FUNCTION "Gest Automatico" : VOID
TITLE =Gestione Ciclo Automatico
AUTHOR : MassimoZ
FAMILY : NovaSrl
VERSION : 0.1

BEGIN
NETWORK
TITLE =Condizioni per Ciclo

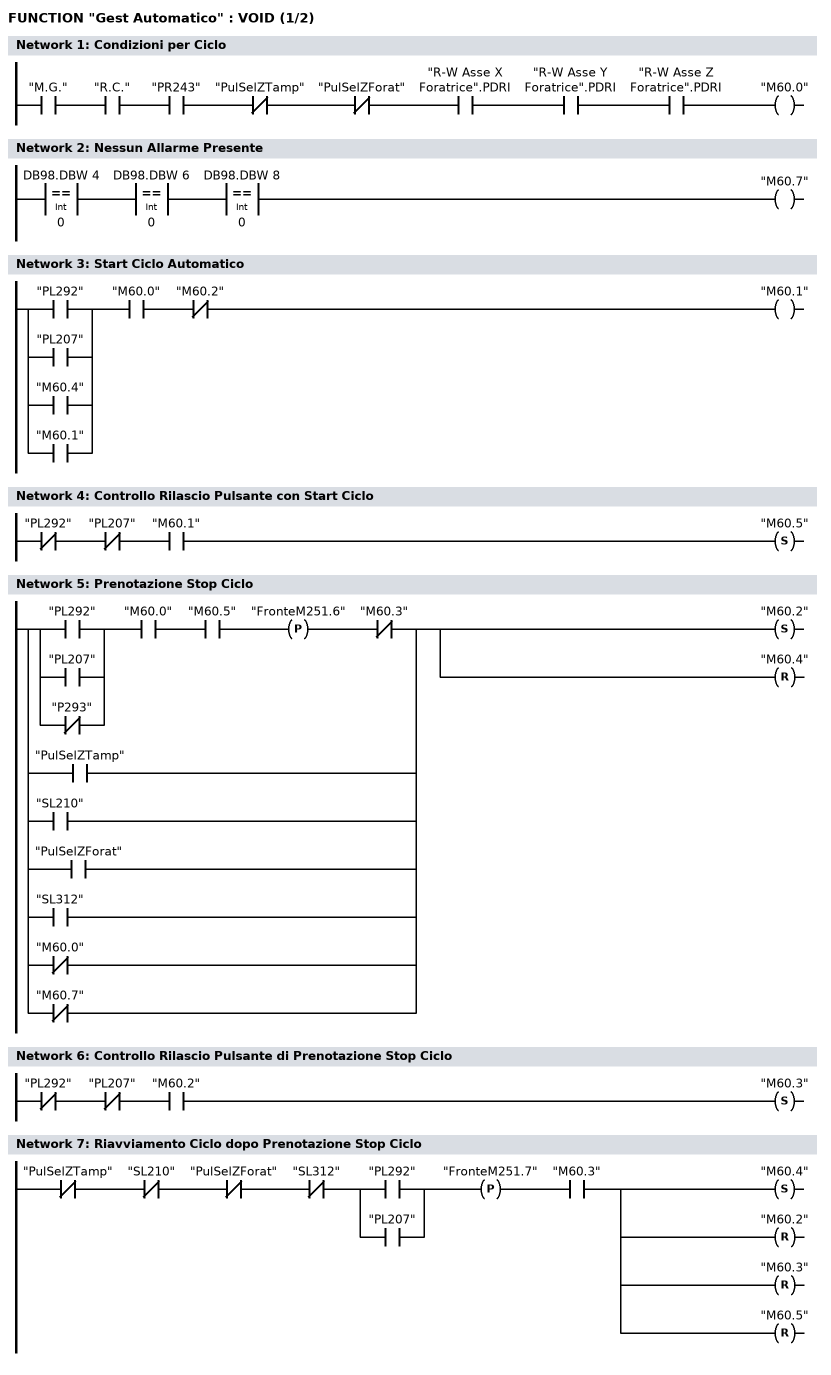
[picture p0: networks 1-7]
      U     "M.G.";
      U     "R.C.";
      U     "PR243";
      UN    "PulSelZTamp";
      UN    "PulSelZForat";
      U     "R-W Asse X Foratrice".PDRI;
      U     "R-W Asse Y Foratrice".PDRI;
      U     "R-W Asse Z Foratrice".PDRI;
      =     "M60.0";
NETWORK
TITLE =Nessun Allarme Presente

      U(    ;
      L     DB98.DBW    4;
      L     0;
      ==I   ;
      )     ;
      U(    ;
      L     DB98.DBW    6;
      L     0;
      ==I   ;
      )     ;
      U(    ;
      L     DB98.DBW    8;
      L     0;
      ==I   ;
      )     ;
      =     "M60.7";
NETWORK
TITLE =Start Ciclo Automatico

      U(    ;
      O     "PL292";
      O     "PL207";
      O     "M60.4";
      O     "M60.1";
      )     ;
      U     "M60.0";
      UN    "M60.2";
      =     "M60.1";
NETWORK
TITLE =Controllo Rilascio Pulsante con Start Ciclo

      UN    "PL292";
      UN    "PL207";
      U     "M60.1";
      S     "M60.5";
NETWORK
TITLE =Prenotazione Stop Ciclo

      U(    ;
      O     "PL292";
      O     "PL207";
      ON    "P293";
      )     ;
      U     "M60.0";
      U     "M60.5";
      FP    "FronteM251.6";
      UN    "M60.3";
      O     "PulSelZTamp";
      O     "SL210";
      O     "PulSelZForat";
      O     "SL312";
      ON    "M60.0";
      ON    "M60.7";
      S     "M60.2";
      R     "M60.4";
NETWORK
TITLE =Controllo Rilascio Pulsante di Prenotazione Stop Ciclo

      UN    "PL292";
      UN    "PL207";
      U     "M60.2";
      S     "M60.3";
NETWORK
TITLE =Riavviamento Ciclo dopo Prenotazione Stop Ciclo

      UN    "PulSelZTamp";
      UN    "SL210";
      UN    "PulSelZForat";
      UN    "SL312";
      U(    ;
      O     "PL292";
      O     "PL207";
      )     ;
      FP    "FronteM251.7";
      U     "M60.3";
      S     "M60.4";
      R     "M60.2";
      R     "M60.3";
      R     "M60.5";
NETWORK
TITLE =Svuotamento Robot Foratrice e Tampografie

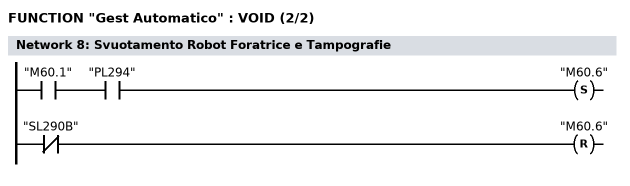
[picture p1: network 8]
      U     "M60.1";
      U     "PL294";
      S     "M60.6";
      UN    "SL290B";
      R     "M60.6";
      NOP   0;
NETWORK
TITLE ======== Ciclo Automatico Zona Foratrice =======



NETWORK
TITLE =Presenza Pezzo in Entrata Zona Foratrice

      U(    ;
      UN    "SL290";
      U     "SL290B";
      U     "FT137";
      L     S5T#1S;
      SE    T     30;
      NOP   0;
      NOP   0;
      NOP   0;
      U     T     30;
      )     ;
      L     S5T#2S;
      SA    T     31;
      NOP   0;
      NOP   0;
      NOP   0;
      U     T     31;
      =     "M61.0";
NETWORK
TITLE =Presenza Pezzo Zona Foratrice

      U(    ;
      UN    "SL290";
      U     "SL290B";
      U     "FT144";
      L     S5T#1S;
      SE    T     32;
      NOP   0;
      NOP   0;
      NOP   0;
      U     T     32;
      )     ;
      L     S5T#200MS;
      SA    T     33;
      NOP   0;
      NOP   0;
      NOP   0;
      U     T     33;
      =     "M61.1";
NETWORK
TITLE =Presenza Pezzo Zona Ribaltatore

      U(    ;
      UN    "SL290";
      U     "SL290B";
      U     "FT146";
      L     S5T#1S500MS;
      SE    T     34;
      NOP   0;
      NOP   0;
      NOP   0;
      U     T     34;
      )     ;
      L     S5T#200MS;
      SA    T     35;
      NOP   0;
      NOP   0;
      NOP   0;
      U     T     35;
      =     "M61.2";
NETWORK
TITLE =Com Aut Start Motore Nastro Orizzontale

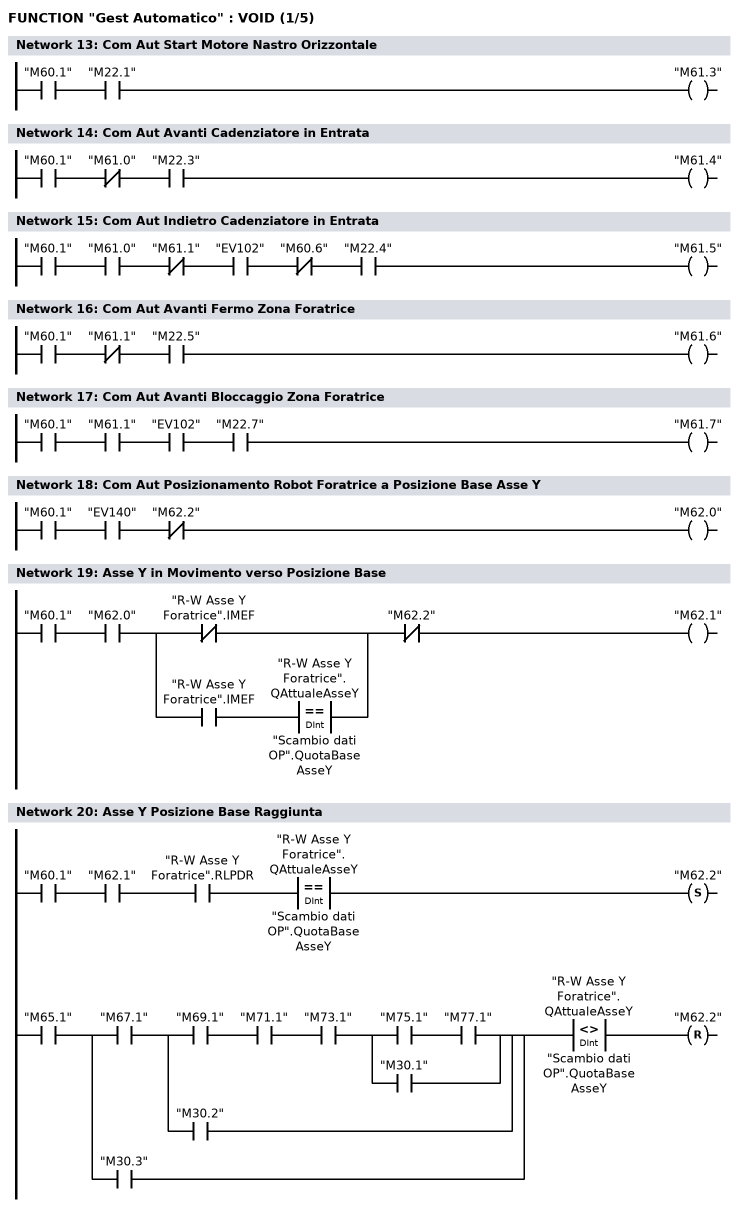
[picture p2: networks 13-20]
      U     "M60.1";
      U     "M22.1";
      =     "M61.3";
NETWORK
TITLE =Com Aut Avanti Cadenziatore in Entrata

      U     "M60.1";
      UN    "M61.0";
      U     "M22.3";
      =     "M61.4";
NETWORK
TITLE =Com Aut Indietro Cadenziatore in Entrata

      U     "M60.1";
      U     "M61.0";
      UN    "M61.1";
      U     "EV102";
      UN    "M60.6";
      U     "M22.4";
      =     "M61.5";
NETWORK
TITLE =Com Aut Avanti Fermo Zona Foratrice

      U     "M60.1";
      UN    "M61.1";
      U     "M22.5";
      =     "M61.6";
NETWORK
TITLE =Com Aut Avanti Bloccaggio Zona Foratrice

      U     "M60.1";
      U     "M61.1";
      U     "EV102";
      U     "M22.7";
      =     "M61.7";
NETWORK
TITLE =Com Aut Posizionamento Robot Foratrice a Posizione Base Asse Y

      U     "M60.1";
      U     "EV140";
      UN    "M62.2";
      =     "M62.0";
NETWORK
TITLE =Asse Y in Movimento verso Posizione Base

      U     "M60.1";
      U     "M62.0";
      U(    ;
      ON    "R-W Asse Y Foratrice".IMEF;
      O     ;
      U     "R-W Asse Y Foratrice".IMEF;
      U(    ;
      L     "R-W Asse Y Foratrice".QAttualeAsseY;
      L     "Scambio dati OP".QuotaBaseAsseY;
      ==D   ;
      )     ;
      )     ;
      UN    "M62.2";
      =     "M62.1";
NETWORK
TITLE =Asse Y Posizione Base Raggiunta

      U     "M60.1";
      U     "M62.1";
      U     "R-W Asse Y Foratrice".RLPDR;
      U(    ;
      L     "R-W Asse Y Foratrice".QAttualeAsseY;
      L     "Scambio dati OP".QuotaBaseAsseY;
      ==D   ;
      )     ;
      S     "M62.2";
      U     "M65.1";
      U(    ;
      U     "M67.1";
      U(    ;
      U     "M69.1";
      U     "M71.1";
      U     "M73.1";
      U(    ;
      U     "M75.1";
      U     "M77.1";
      O     "M30.1";
      )     ;
      O     "M30.2";
      )     ;
      O     "M30.3";
      )     ;
      U(    ;
      L     "R-W Asse Y Foratrice".QAttualeAsseY;
      L     "Scambio dati OP".QuotaBaseAsseY;
      <>D   ;
      )     ;
      R     "M62.2";
      NOP   0;
NETWORK
TITLE =Com Aut Posizionamento Robot Foratrice a Posizione Base Asse X

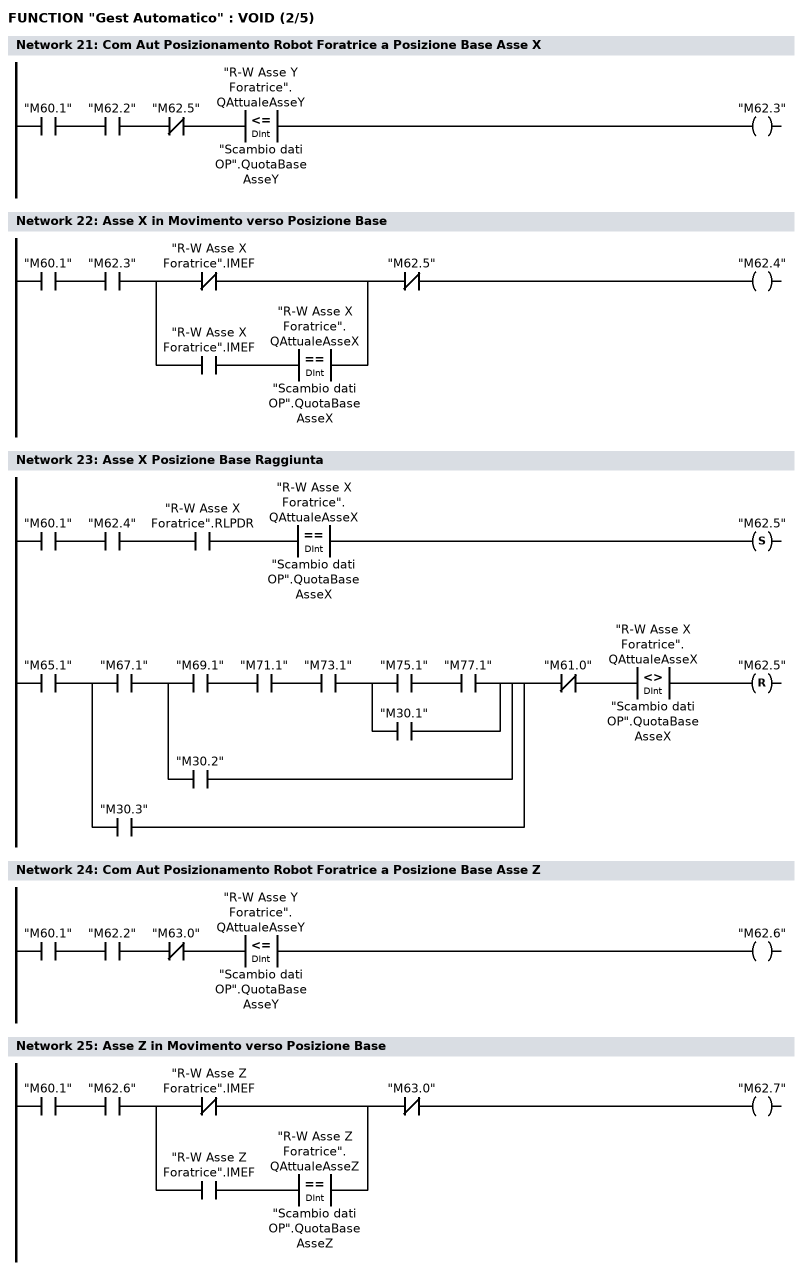
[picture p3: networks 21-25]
      U     "M60.1";
      U     "M62.2";
      UN    "M62.5";
      U(    ;
      L     "R-W Asse Y Foratrice".QAttualeAsseY;
      L     "Scambio dati OP".QuotaBaseAsseY;
      <=D   ;
      )     ;
      =     "M62.3";
NETWORK
TITLE =Asse X in Movimento verso Posizione Base

      U     "M60.1";
      U     "M62.3";
      U(    ;
      ON    "R-W Asse X Foratrice".IMEF;
      O     ;
      U     "R-W Asse X Foratrice".IMEF;
      U(    ;
      L     "R-W Asse X Foratrice".QAttualeAsseX;
      L     "Scambio dati OP".QuotaBaseAsseX;
      ==D   ;
      )     ;
      )     ;
      UN    "M62.5";
      =     "M62.4";
NETWORK
TITLE =Asse X Posizione Base Raggiunta

      U     "M60.1";
      U     "M62.4";
      U     "R-W Asse X Foratrice".RLPDR;
      U(    ;
      L     "R-W Asse X Foratrice".QAttualeAsseX;
      L     "Scambio dati OP".QuotaBaseAsseX;
      ==D   ;
      )     ;
      S     "M62.5";
      U     "M65.1";
      U(    ;
      U     "M67.1";
      U(    ;
      U     "M69.1";
      U     "M71.1";
      U     "M73.1";
      U(    ;
      U     "M75.1";
      U     "M77.1";
      O     "M30.1";
      )     ;
      O     "M30.2";
      )     ;
      O     "M30.3";
      )     ;
      UN    "M61.0";
      U(    ;
      L     "R-W Asse X Foratrice".QAttualeAsseX;
      L     "Scambio dati OP".QuotaBaseAsseX;
      <>D   ;
      )     ;
      R     "M62.5";
      NOP   0;
NETWORK
TITLE =Com Aut Posizionamento Robot Foratrice a Posizione Base Asse Z

      U     "M60.1";
      U     "M62.2";
      UN    "M63.0";
      U(    ;
      L     "R-W Asse Y Foratrice".QAttualeAsseY;
      L     "Scambio dati OP".QuotaBaseAsseY;
      <=D   ;
      )     ;
      =     "M62.6";
NETWORK
TITLE =Asse Z in Movimento verso Posizione Base

      U     "M60.1";
      U     "M62.6";
      U(    ;
      ON    "R-W Asse Z Foratrice".IMEF;
      O     ;
      U     "R-W Asse Z Foratrice".IMEF;
      U(    ;
      L     "R-W Asse Z Foratrice".QAttualeAsseZ;
      L     "Scambio dati OP".QuotaBaseAsseZ;
      ==D   ;
      )     ;
      )     ;
      UN    "M63.0";
      =     "M62.7";
NETWORK
TITLE =Asse Z Posizione Base Raggiunta

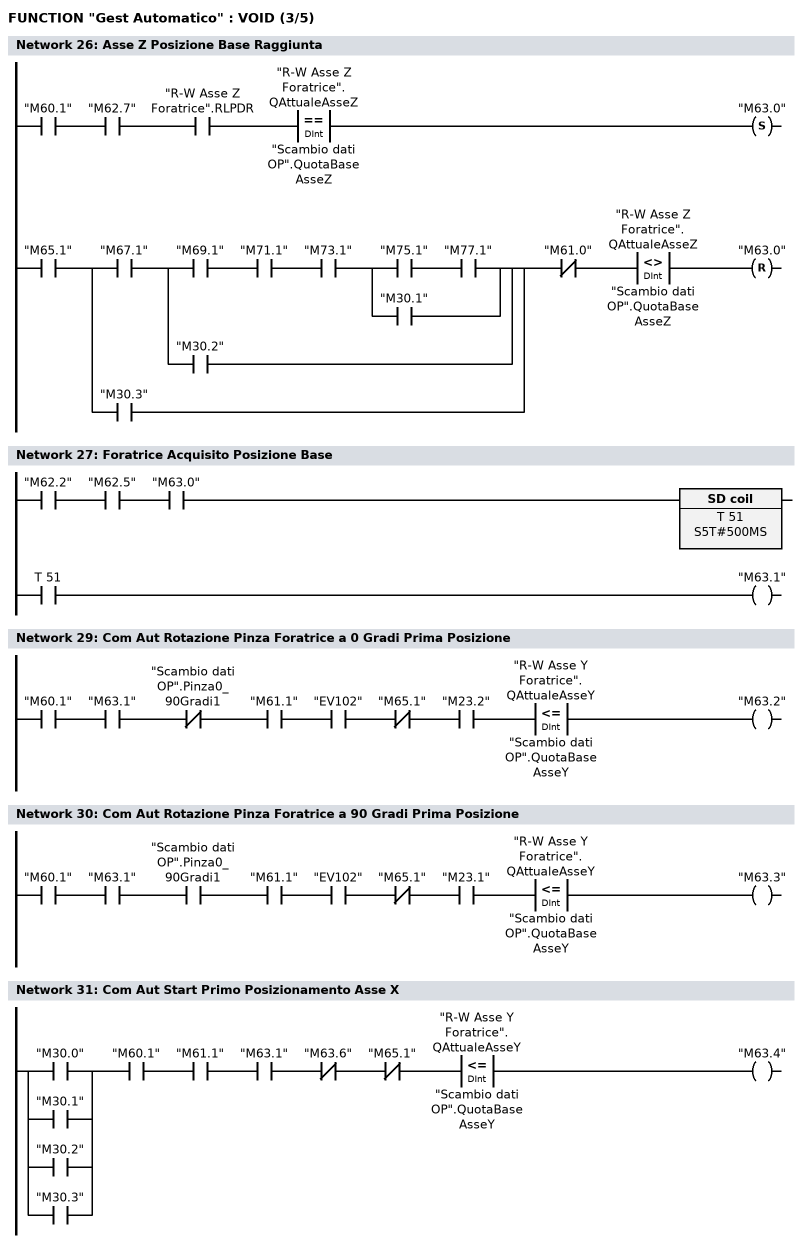
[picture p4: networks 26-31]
      U     "M60.1";
      U     "M62.7";
      U     "R-W Asse Z Foratrice".RLPDR;
      U(    ;
      L     "R-W Asse Z Foratrice".QAttualeAsseZ;
      L     "Scambio dati OP".QuotaBaseAsseZ;
      ==D   ;
      )     ;
      S     "M63.0";
      U     "M65.1";
      U(    ;
      U     "M67.1";
      U(    ;
      U     "M69.1";
      U     "M71.1";
      U     "M73.1";
      U(    ;
      U     "M75.1";
      U     "M77.1";
      O     "M30.1";
      )     ;
      O     "M30.2";
      )     ;
      O     "M30.3";
      )     ;
      UN    "M61.0";
      U(    ;
      L     "R-W Asse Z Foratrice".QAttualeAsseZ;
      L     "Scambio dati OP".QuotaBaseAsseZ;
      <>D   ;
      )     ;
      R     "M63.0";
      NOP   0;
NETWORK
TITLE =Foratrice Acquisito Posizione Base

      U     "M62.2";
      U     "M62.5";
      U     "M63.0";
      L     S5T#500MS;
      SE    T     51;
      NOP   0;
      NOP   0;
      NOP   0;
      U     T     51;
      =     "M63.1";
NETWORK
TITLE ======== Primo Posizionamento Foratrice =======



NETWORK
TITLE =Com Aut Rotazione Pinza Foratrice a 0 Gradi Prima Posizione

      U     "M60.1";
      U     "M63.1";
      UN    "Scambio dati OP".Pinza0_90Gradi1;
      U     "M61.1";
      U     "EV102";
      UN    "M65.1";
      U     "M23.2";
      U(    ;
      L     "R-W Asse Y Foratrice".QAttualeAsseY;
      L     "Scambio dati OP".QuotaBaseAsseY;
      <=D   ;
      )     ;
      =     "M63.2";
NETWORK
TITLE =Com Aut Rotazione Pinza Foratrice a 90 Gradi Prima Posizione

      U     "M60.1";
      U     "M63.1";
      U     "Scambio dati OP".Pinza0_90Gradi1;
      U     "M61.1";
      U     "EV102";
      UN    "M65.1";
      U     "M23.1";
      U(    ;
      L     "R-W Asse Y Foratrice".QAttualeAsseY;
      L     "Scambio dati OP".QuotaBaseAsseY;
      <=D   ;
      )     ;
      =     "M63.3";
NETWORK
TITLE =Com Aut Start Primo Posizionamento Asse X

      U(    ;
      O     "M30.0";
      O     "M30.1";
      O     "M30.2";
      O     "M30.3";
      )     ;
      U     "M60.1";
      U     "M61.1";
      U     "M63.1";
      UN    "M63.6";
      UN    "M65.1";
      U(    ;
      L     "R-W Asse Y Foratrice".QAttualeAsseY;
      L     "Scambio dati OP".QuotaBaseAsseY;
      <=D   ;
      )     ;
      =     "M63.4";
NETWORK
TITLE =Asse X in Movimento verso il Primo Posizionamento

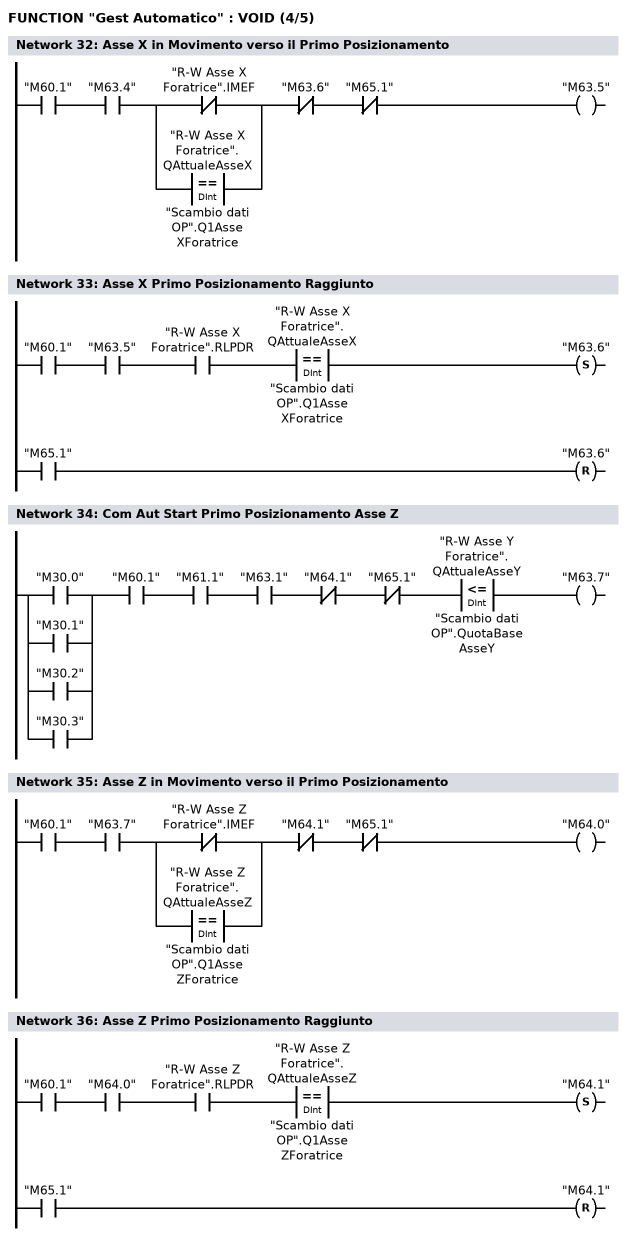
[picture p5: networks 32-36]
      U     "M60.1";
      U     "M63.4";
      U(    ;
      ON    "R-W Asse X Foratrice".IMEF;
      O(    ;
      L     "R-W Asse X Foratrice".QAttualeAsseX;
      L     "Scambio dati OP".Q1AsseXForatrice;
      ==D   ;
      )     ;
      )     ;
      UN    "M63.6";
      UN    "M65.1";
      =     "M63.5";
NETWORK
TITLE =Asse X Primo Posizionamento Raggiunto

      U     "M60.1";
      U     "M63.5";
      U     "R-W Asse X Foratrice".RLPDR;
      U(    ;
      L     "R-W Asse X Foratrice".QAttualeAsseX;
      L     "Scambio dati OP".Q1AsseXForatrice;
      ==D   ;
      )     ;
      S     "M63.6";
      U     "M65.1";
      R     "M63.6";
      NOP   0;
NETWORK
TITLE =Com Aut Start Primo Posizionamento Asse Z

      U(    ;
      O     "M30.0";
      O     "M30.1";
      O     "M30.2";
      O     "M30.3";
      )     ;
      U     "M60.1";
      U     "M61.1";
      U     "M63.1";
      UN    "M64.1";
      UN    "M65.1";
      U(    ;
      L     "R-W Asse Y Foratrice".QAttualeAsseY;
      L     "Scambio dati OP".QuotaBaseAsseY;
      <=D   ;
      )     ;
      =     "M63.7";
NETWORK
TITLE =Asse Z in Movimento verso il Primo Posizionamento

      U     "M60.1";
      U     "M63.7";
      U(    ;
      ON    "R-W Asse Z Foratrice".IMEF;
      O(    ;
      L     "R-W Asse Z Foratrice".QAttualeAsseZ;
      L     "Scambio dati OP".Q1AsseZForatrice;
      ==D   ;
      )     ;
      )     ;
      UN    "M64.1";
      UN    "M65.1";
      =     "M64.0";
NETWORK
TITLE =Asse Z Primo Posizionamento Raggiunto

      U     "M60.1";
      U     "M64.0";
      U     "R-W Asse Z Foratrice".RLPDR;
      U(    ;
      L     "R-W Asse Z Foratrice".QAttualeAsseZ;
      L     "Scambio dati OP".Q1AsseZForatrice;
      ==D   ;
      )     ;
      S     "M64.1";
      U     "M65.1";
      R     "M64.1";
      NOP   0;
NETWORK
TITLE =Com Aut Start Primo Posizionamento Asse Y

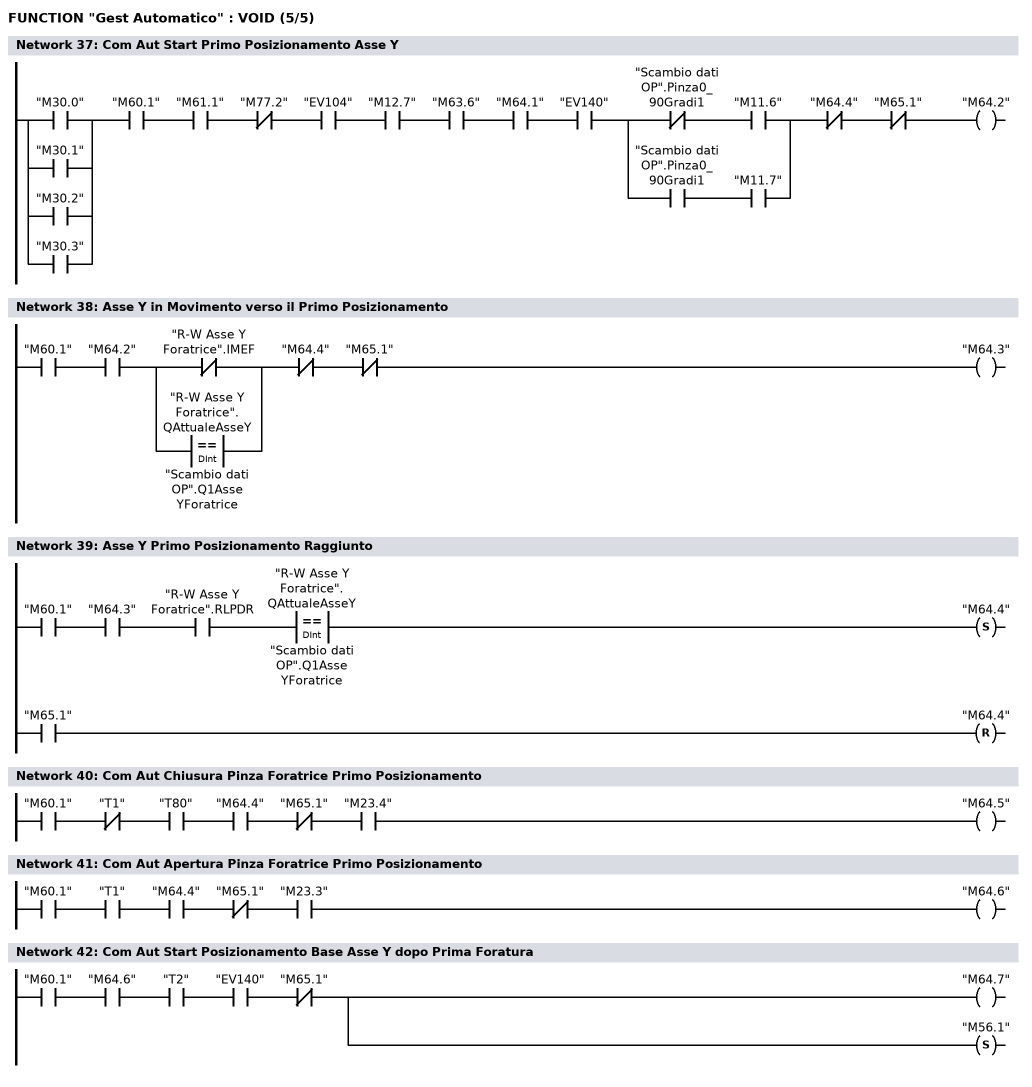
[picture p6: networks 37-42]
      U(    ;
      O     "M30.0";
      O     "M30.1";
      O     "M30.2";
      O     "M30.3";
      )     ;
      U     "M60.1";
      U     "M61.1";
      UN    "M77.2";
      U     "EV104";
      U     "M12.7";
      U     "M63.6";
      U     "M64.1";
      U     "EV140";
      U(    ;
      UN    "Scambio dati OP".Pinza0_90Gradi1;
      U     "M11.6";
      O     ;
      U     "Scambio dati OP".Pinza0_90Gradi1;
      U     "M11.7";
      )     ;
      UN    "M64.4";
      UN    "M65.1";
      =     "M64.2";
NETWORK
TITLE =Asse Y in Movimento verso il Primo Posizionamento

      U     "M60.1";
      U     "M64.2";
      U(    ;
      ON    "R-W Asse Y Foratrice".IMEF;
      O(    ;
      L     "R-W Asse Y Foratrice".QAttualeAsseY;
      L     "Scambio dati OP".Q1AsseYForatrice;
      ==D   ;
      )     ;
      )     ;
      UN    "M64.4";
      UN    "M65.1";
      =     "M64.3";
NETWORK
TITLE =Asse Y Primo Posizionamento Raggiunto

      U     "M60.1";
      U     "M64.3";
      U     "R-W Asse Y Foratrice".RLPDR;
      U(    ;
      L     "R-W Asse Y Foratrice".QAttualeAsseY;
      L     "Scambio dati OP".Q1AsseYForatrice;
      ==D   ;
      )     ;
      S     "M64.4";
      U     "M65.1";
      R     "M64.4";
      NOP   0;
NETWORK
TITLE =Com Aut Chiusura Pinza Foratrice Primo Posizionamento

      U     "M60.1";
      UN    "T1";
      U     "T80";
      U     "M64.4";
      UN    "M65.1";
      U     "M23.4";
      =     "M64.5";
NETWORK
TITLE =Com Aut Apertura Pinza Foratrice Primo Posizionamento

      U     "M60.1";
      U     "T1";
      U     "M64.4";
      UN    "M65.1";
      U     "M23.3";
      =     "M64.6";
NETWORK
TITLE =Com Aut Start Posizionamento Base Asse Y dopo Prima Foratura

      U     "M60.1";
      U     "M64.6";
      U     "T2";
      U     "EV140";
      UN    "M65.1";
      =     "M64.7";
      S     "M56.1";
NETWORK
TITLE =

      U     "M56.1";
      =     L      0.0;
      U(    ;
      U     L      0.0;
      L     "Scambio dati OP".TempChiPinzaFor;
      SE    T     82;
      NOP   0;
      NOP   0;
      NOP   0;
      U     T     82;
      )     ;
      L     "Scambio dati OP".TempApePinzaFor;
      SE    T     83;
      NOP   0;
      NOP   0;
      NOP   0;
      NOP   0;
      U     L      0.0;
      UN    T     82;
      U     "M56.0";
      =     "M57.1";
      U     L      0.0;
      U     T     82;
      UN    T     83;
      U     "M56.0";
      =     "M58.1";
NETWORK
TITLE =Flag fine ciclo foratura 1

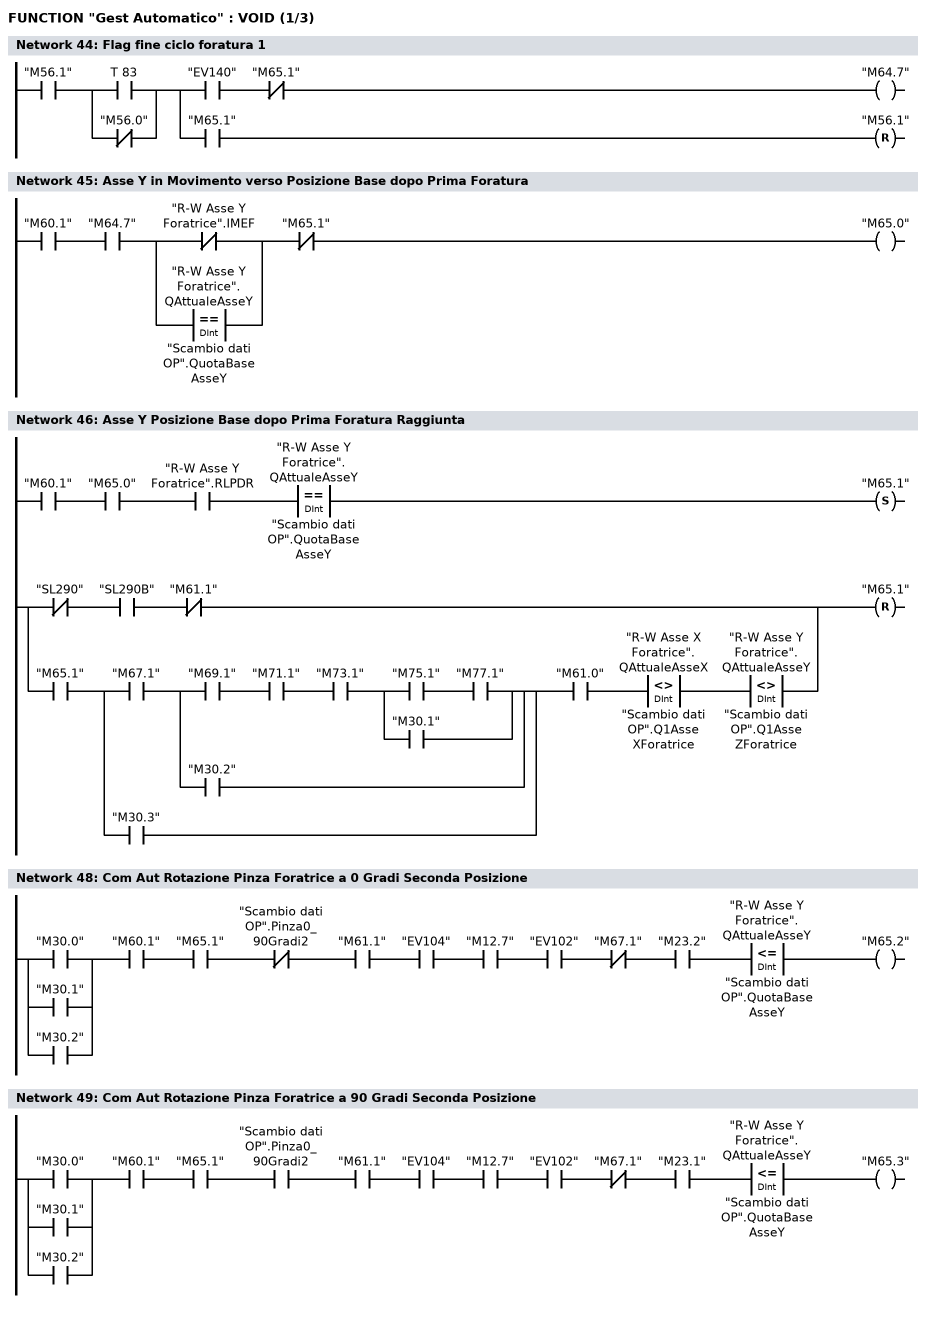
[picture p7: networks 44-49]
      U     "M56.1";
      U(    ;
      O     T     83;
      ON    "M56.0";
      )     ;
      =     L      0.0;
      U     L      0.0;
      U     "EV140";
      UN    "M65.1";
      =     "M64.7";
      U     L      0.0;
      U     "M65.1";
      R     "M56.1";
NETWORK
TITLE =Asse Y in Movimento verso Posizione Base dopo Prima Foratura

      U     "M60.1";
      U     "M64.7";
      U(    ;
      ON    "R-W Asse Y Foratrice".IMEF;
      O(    ;
      L     "R-W Asse Y Foratrice".QAttualeAsseY;
      L     "Scambio dati OP".QuotaBaseAsseY;
      ==D   ;
      )     ;
      )     ;
      UN    "M65.1";
      =     "M65.0";
NETWORK
TITLE =Asse Y Posizione Base dopo Prima Foratura Raggiunta

      U     "M60.1";
      U     "M65.0";
      U     "R-W Asse Y Foratrice".RLPDR;
      U(    ;
      L     "R-W Asse Y Foratrice".QAttualeAsseY;
      L     "Scambio dati OP".QuotaBaseAsseY;
      ==D   ;
      )     ;
      S     "M65.1";
      U(    ;
      UN    "SL290";
      U     "SL290B";
      UN    "M61.1";
      O     ;
      U     "M65.1";
      U(    ;
      U     "M67.1";
      U(    ;
      U     "M69.1";
      U     "M71.1";
      U     "M73.1";
      U(    ;
      U     "M75.1";
      U     "M77.1";
      O     "M30.1";
      )     ;
      O     "M30.2";
      )     ;
      O     "M30.3";
      )     ;
      U     "M61.0";
      U(    ;
      L     "R-W Asse X Foratrice".QAttualeAsseX;
      L     "Scambio dati OP".Q1AsseXForatrice;
      <>D   ;
      )     ;
      U(    ;
      L     "R-W Asse Y Foratrice".QAttualeAsseY;
      L     "Scambio dati OP".Q1AsseZForatrice;
      <>D   ;
      )     ;
      )     ;
      R     "M65.1";
      NOP   0;
NETWORK
TITLE ======== Secondo Posizionamento Foratrice =======



NETWORK
TITLE =Com Aut Rotazione Pinza Foratrice a 0 Gradi Seconda Posizione

      U(    ;
      O     "M30.0";
      O     "M30.1";
      O     "M30.2";
      )     ;
      U     "M60.1";
      U     "M65.1";
      UN    "Scambio dati OP".Pinza0_90Gradi2;
      U     "M61.1";
      U     "EV104";
      U     "M12.7";
      U     "EV102";
      UN    "M67.1";
      U     "M23.2";
      U(    ;
      L     "R-W Asse Y Foratrice".QAttualeAsseY;
      L     "Scambio dati OP".QuotaBaseAsseY;
      <=D   ;
      )     ;
      =     "M65.2";
NETWORK
TITLE =Com Aut Rotazione Pinza Foratrice a 90 Gradi Seconda Posizione

      U(    ;
      O     "M30.0";
      O     "M30.1";
      O     "M30.2";
      )     ;
      U     "M60.1";
      U     "M65.1";
      U     "Scambio dati OP".Pinza0_90Gradi2;
      U     "M61.1";
      U     "EV104";
      U     "M12.7";
      U     "EV102";
      UN    "M67.1";
      U     "M23.1";
      U(    ;
      L     "R-W Asse Y Foratrice".QAttualeAsseY;
      L     "Scambio dati OP".QuotaBaseAsseY;
      <=D   ;
      )     ;
      =     "M65.3";
NETWORK
TITLE =Com Aut Start Secondo Posizionamento Asse X

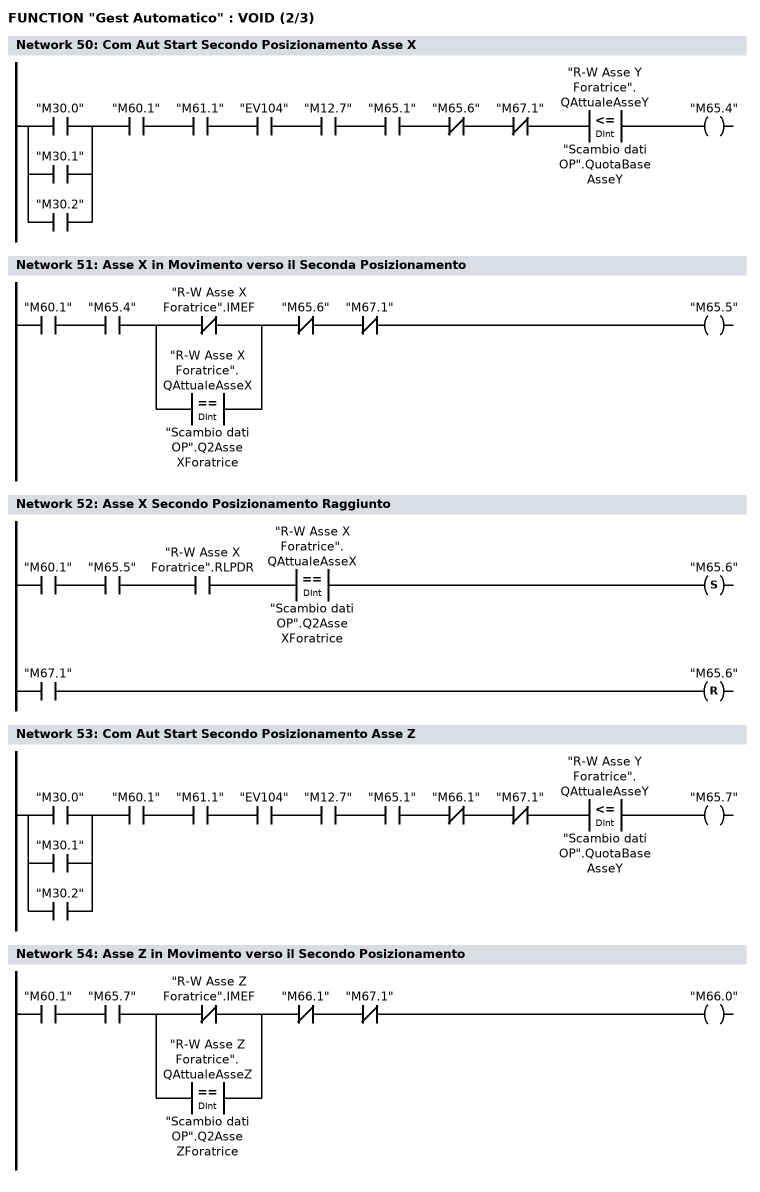
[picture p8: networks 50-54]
      U(    ;
      O     "M30.0";
      O     "M30.1";
      O     "M30.2";
      )     ;
      U     "M60.1";
      U     "M61.1";
      U     "EV104";
      U     "M12.7";
      U     "M65.1";
      UN    "M65.6";
      UN    "M67.1";
      U(    ;
      L     "R-W Asse Y Foratrice".QAttualeAsseY;
      L     "Scambio dati OP".QuotaBaseAsseY;
      <=D   ;
      )     ;
      =     "M65.4";
NETWORK
TITLE =Asse X in Movimento verso il Seconda Posizionamento

      U     "M60.1";
      U     "M65.4";
      U(    ;
      ON    "R-W Asse X Foratrice".IMEF;
      O(    ;
      L     "R-W Asse X Foratrice".QAttualeAsseX;
      L     "Scambio dati OP".Q2AsseXForatrice;
      ==D   ;
      )     ;
      )     ;
      UN    "M65.6";
      UN    "M67.1";
      =     "M65.5";
NETWORK
TITLE =Asse X Secondo Posizionamento Raggiunto

      U     "M60.1";
      U     "M65.5";
      U     "R-W Asse X Foratrice".RLPDR;
      U(    ;
      L     "R-W Asse X Foratrice".QAttualeAsseX;
      L     "Scambio dati OP".Q2AsseXForatrice;
      ==D   ;
      )     ;
      S     "M65.6";
      U     "M67.1";
      R     "M65.6";
      NOP   0;
NETWORK
TITLE =Com Aut Start Secondo Posizionamento Asse Z

      U(    ;
      O     "M30.0";
      O     "M30.1";
      O     "M30.2";
      )     ;
      U     "M60.1";
      U     "M61.1";
      U     "EV104";
      U     "M12.7";
      U     "M65.1";
      UN    "M66.1";
      UN    "M67.1";
      U(    ;
      L     "R-W Asse Y Foratrice".QAttualeAsseY;
      L     "Scambio dati OP".QuotaBaseAsseY;
      <=D   ;
      )     ;
      =     "M65.7";
NETWORK
TITLE =Asse Z in Movimento verso il Secondo Posizionamento

      U     "M60.1";
      U     "M65.7";
      U(    ;
      ON    "R-W Asse Z Foratrice".IMEF;
      O(    ;
      L     "R-W Asse Z Foratrice".QAttualeAsseZ;
      L     "Scambio dati OP".Q2AsseZForatrice;
      ==D   ;
      )     ;
      )     ;
      UN    "M66.1";
      UN    "M67.1";
      =     "M66.0";
NETWORK
TITLE =Asse Z Secondo Posizionamento Raggiunto

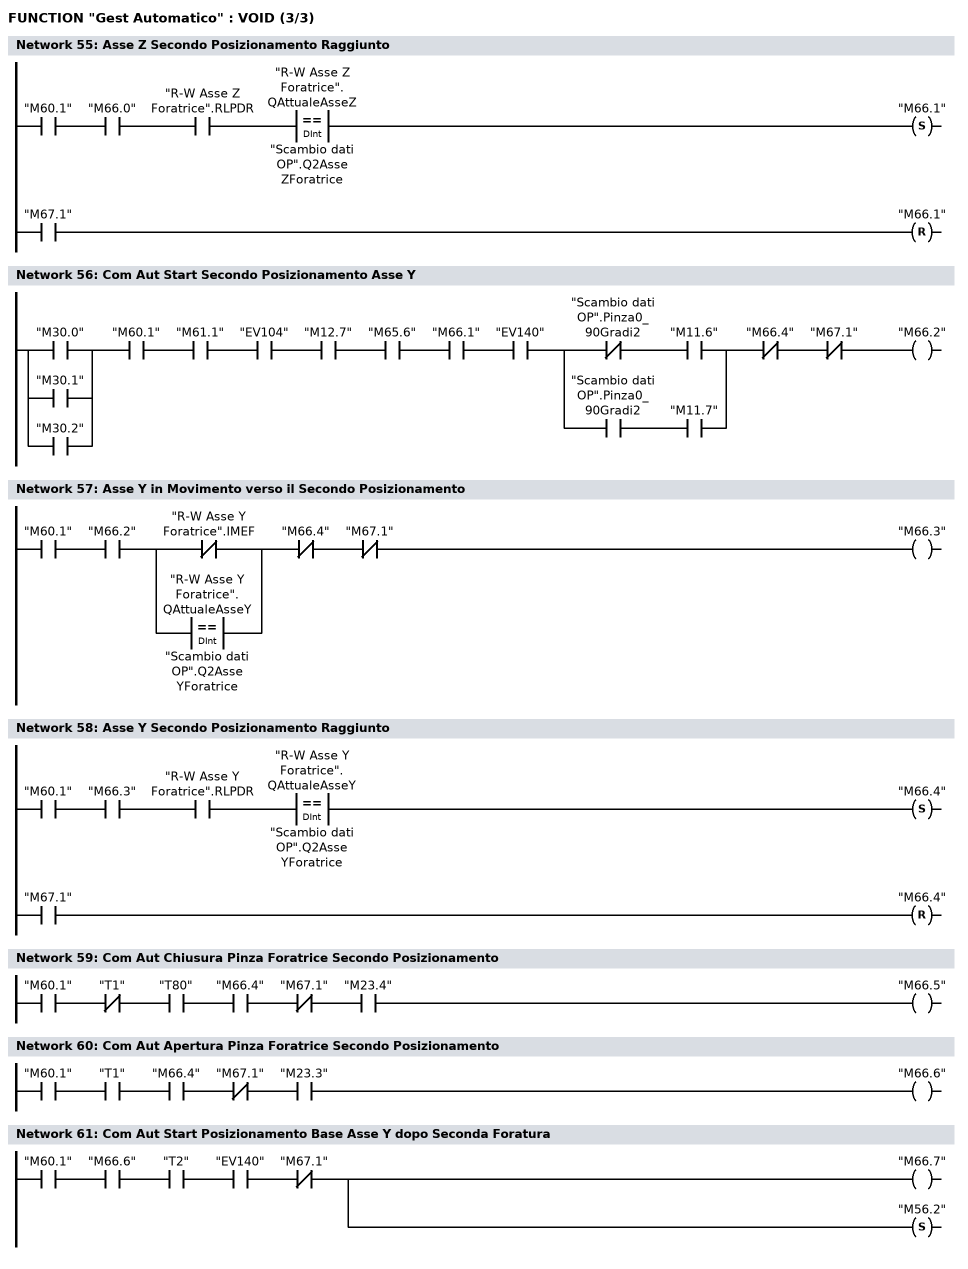
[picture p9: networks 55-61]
      U     "M60.1";
      U     "M66.0";
      U     "R-W Asse Z Foratrice".RLPDR;
      U(    ;
      L     "R-W Asse Z Foratrice".QAttualeAsseZ;
      L     "Scambio dati OP".Q2AsseZForatrice;
      ==D   ;
      )     ;
      S     "M66.1";
      U     "M67.1";
      R     "M66.1";
      NOP   0;
NETWORK
TITLE =Com Aut Start Secondo Posizionamento Asse Y

      U(    ;
      O     "M30.0";
      O     "M30.1";
      O     "M30.2";
      )     ;
      U     "M60.1";
      U     "M61.1";
      U     "EV104";
      U     "M12.7";
      U     "M65.6";
      U     "M66.1";
      U     "EV140";
      U(    ;
      UN    "Scambio dati OP".Pinza0_90Gradi2;
      U     "M11.6";
      O     ;
      U     "Scambio dati OP".Pinza0_90Gradi2;
      U     "M11.7";
      )     ;
      UN    "M66.4";
      UN    "M67.1";
      =     "M66.2";
NETWORK
TITLE =Asse Y in Movimento verso il Secondo Posizionamento

      U     "M60.1";
      U     "M66.2";
      U(    ;
      ON    "R-W Asse Y Foratrice".IMEF;
      O(    ;
      L     "R-W Asse Y Foratrice".QAttualeAsseY;
      L     "Scambio dati OP".Q2AsseYForatrice;
      ==D   ;
      )     ;
      )     ;
      UN    "M66.4";
      UN    "M67.1";
      =     "M66.3";
NETWORK
TITLE =Asse Y Secondo Posizionamento Raggiunto

      U     "M60.1";
      U     "M66.3";
      U     "R-W Asse Y Foratrice".RLPDR;
      U(    ;
      L     "R-W Asse Y Foratrice".QAttualeAsseY;
      L     "Scambio dati OP".Q2AsseYForatrice;
      ==D   ;
      )     ;
      S     "M66.4";
      U     "M67.1";
      R     "M66.4";
      NOP   0;
NETWORK
TITLE =Com Aut Chiusura Pinza Foratrice Secondo Posizionamento

      U     "M60.1";
      UN    "T1";
      U     "T80";
      U     "M66.4";
      UN    "M67.1";
      U     "M23.4";
      =     "M66.5";
NETWORK
TITLE =Com Aut Apertura Pinza Foratrice Secondo Posizionamento

      U     "M60.1";
      U     "T1";
      U     "M66.4";
      UN    "M67.1";
      U     "M23.3";
      =     "M66.6";
NETWORK
TITLE =Com Aut Start Posizionamento Base Asse Y dopo Seconda Foratura

      U     "M60.1";
      U     "M66.6";
      U     "T2";
      U     "EV140";
      UN    "M67.1";
      =     "M66.7";
      S     "M56.2";
NETWORK
TITLE =

      U     "M56.2";
      =     L      0.0;
      U(    ;
      U     L      0.0;
      L     "Scambio dati OP".TempChiPinzaFor;
      SE    T     84;
      NOP   0;
      NOP   0;
      NOP   0;
      U     T     84;
      )     ;
      L     "Scambio dati OP".TempApePinzaFor;
      SE    T     85;
      NOP   0;
      NOP   0;
      NOP   0;
      NOP   0;
      U     L      0.0;
      UN    T     84;
      U     "M56.0";
      =     "M57.2";
      U     L      0.0;
      U     T     84;
      UN    T     85;
      U     "M56.0";
      =     "M58.2";
NETWORK
TITLE =Com Aut Start Posizionamento Base Asse Y dopo Seconda Foratura

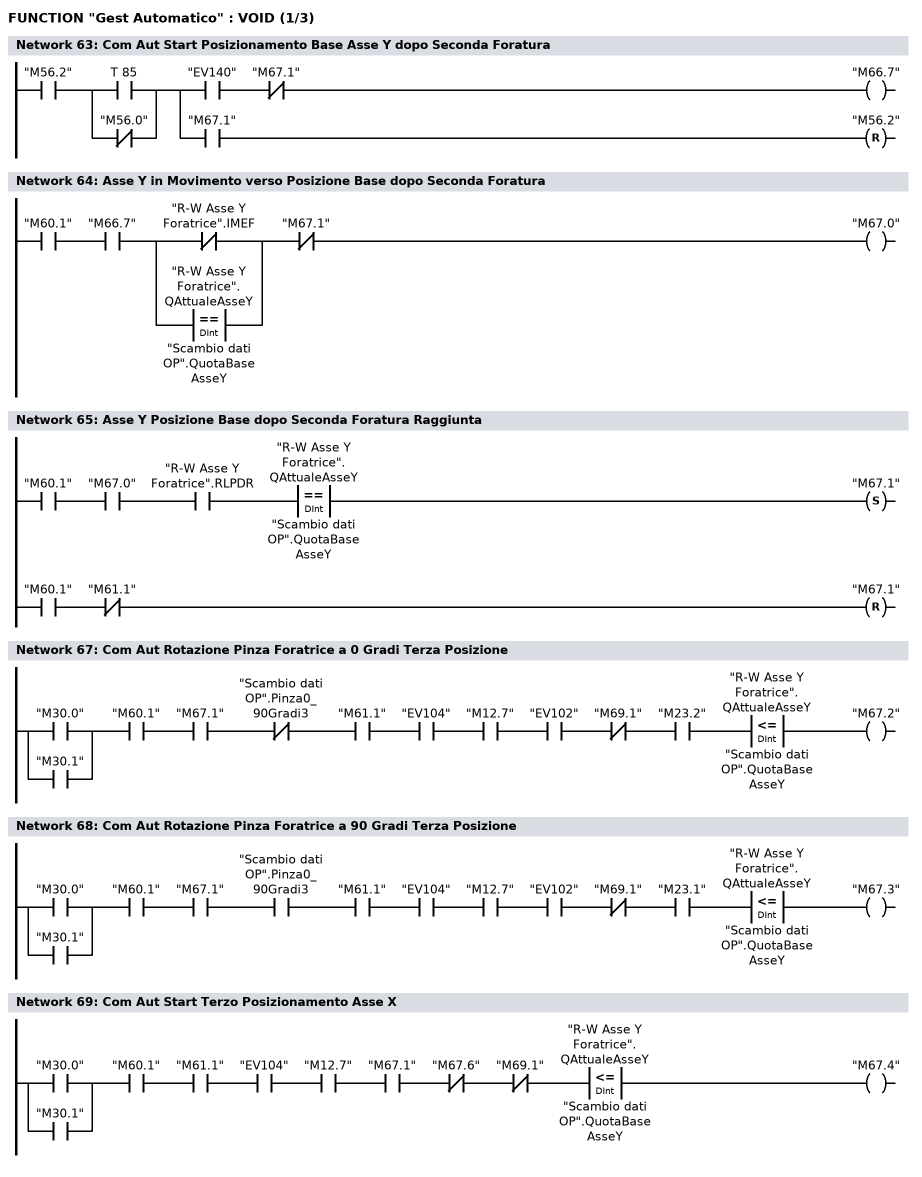
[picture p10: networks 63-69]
      U     "M56.2";
      U(    ;
      O     T     85;
      ON    "M56.0";
      )     ;
      =     L      0.0;
      U     L      0.0;
      U     "EV140";
      UN    "M67.1";
      =     "M66.7";
      U     L      0.0;
      U     "M67.1";
      R     "M56.2";
NETWORK
TITLE =Asse Y in Movimento verso Posizione Base dopo Seconda Foratura

      U     "M60.1";
      U     "M66.7";
      U(    ;
      ON    "R-W Asse Y Foratrice".IMEF;
      O(    ;
      L     "R-W Asse Y Foratrice".QAttualeAsseY;
      L     "Scambio dati OP".QuotaBaseAsseY;
      ==D   ;
      )     ;
      )     ;
      UN    "M67.1";
      =     "M67.0";
NETWORK
TITLE =Asse Y Posizione Base dopo Seconda Foratura Raggiunta

      U     "M60.1";
      U     "M67.0";
      U     "R-W Asse Y Foratrice".RLPDR;
      U(    ;
      L     "R-W Asse Y Foratrice".QAttualeAsseY;
      L     "Scambio dati OP".QuotaBaseAsseY;
      ==D   ;
      )     ;
      S     "M67.1";
      U     "M60.1";
      UN    "M61.1";
      R     "M67.1";
      NOP   0;
NETWORK
TITLE ======== Terzo Posizionamento Foratrice =======



NETWORK
TITLE =Com Aut Rotazione Pinza Foratrice a 0 Gradi Terza Posizione

      U(    ;
      O     "M30.0";
      O     "M30.1";
      )     ;
      U     "M60.1";
      U     "M67.1";
      UN    "Scambio dati OP".Pinza0_90Gradi3;
      U     "M61.1";
      U     "EV104";
      U     "M12.7";
      U     "EV102";
      UN    "M69.1";
      U     "M23.2";
      U(    ;
      L     "R-W Asse Y Foratrice".QAttualeAsseY;
      L     "Scambio dati OP".QuotaBaseAsseY;
      <=D   ;
      )     ;
      =     "M67.2";
NETWORK
TITLE =Com Aut Rotazione Pinza Foratrice a 90 Gradi Terza Posizione

      U(    ;
      O     "M30.0";
      O     "M30.1";
      )     ;
      U     "M60.1";
      U     "M67.1";
      U     "Scambio dati OP".Pinza0_90Gradi3;
      U     "M61.1";
      U     "EV104";
      U     "M12.7";
      U     "EV102";
      UN    "M69.1";
      U     "M23.1";
      U(    ;
      L     "R-W Asse Y Foratrice".QAttualeAsseY;
      L     "Scambio dati OP".QuotaBaseAsseY;
      <=D   ;
      )     ;
      =     "M67.3";
NETWORK
TITLE =Com Aut Start Terzo Posizionamento Asse X

      U(    ;
      O     "M30.0";
      O     "M30.1";
      )     ;
      U     "M60.1";
      U     "M61.1";
      U     "EV104";
      U     "M12.7";
      U     "M67.1";
      UN    "M67.6";
      UN    "M69.1";
      U(    ;
      L     "R-W Asse Y Foratrice".QAttualeAsseY;
      L     "Scambio dati OP".QuotaBaseAsseY;
      <=D   ;
      )     ;
      =     "M67.4";
NETWORK
TITLE =Asse X in Movimento verso il Terzo Posizionamento

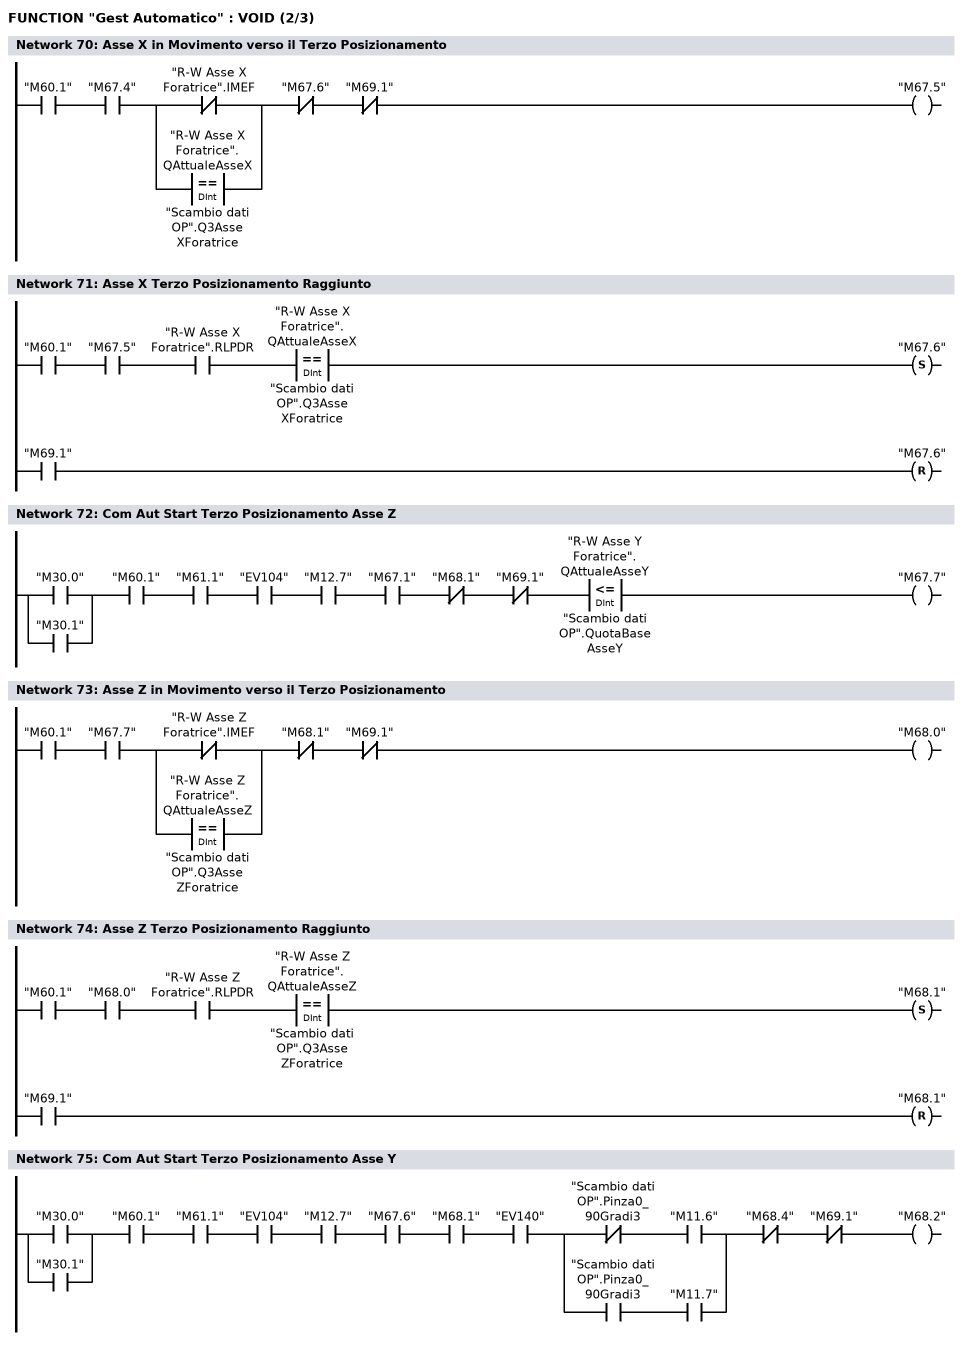
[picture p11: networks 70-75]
      U     "M60.1";
      U     "M67.4";
      U(    ;
      ON    "R-W Asse X Foratrice".IMEF;
      O(    ;
      L     "R-W Asse X Foratrice".QAttualeAsseX;
      L     "Scambio dati OP".Q3AsseXForatrice;
      ==D   ;
      )     ;
      )     ;
      UN    "M67.6";
      UN    "M69.1";
      =     "M67.5";
NETWORK
TITLE =Asse X Terzo Posizionamento Raggiunto

      U     "M60.1";
      U     "M67.5";
      U     "R-W Asse X Foratrice".RLPDR;
      U(    ;
      L     "R-W Asse X Foratrice".QAttualeAsseX;
      L     "Scambio dati OP".Q3AsseXForatrice;
      ==D   ;
      )     ;
      S     "M67.6";
      U     "M69.1";
      R     "M67.6";
      NOP   0;
NETWORK
TITLE =Com Aut Start Terzo Posizionamento Asse Z

      U(    ;
      O     "M30.0";
      O     "M30.1";
      )     ;
      U     "M60.1";
      U     "M61.1";
      U     "EV104";
      U     "M12.7";
      U     "M67.1";
      UN    "M68.1";
      UN    "M69.1";
      U(    ;
      L     "R-W Asse Y Foratrice".QAttualeAsseY;
      L     "Scambio dati OP".QuotaBaseAsseY;
      <=D   ;
      )     ;
      =     "M67.7";
NETWORK
TITLE =Asse Z in Movimento verso il Terzo Posizionamento

      U     "M60.1";
      U     "M67.7";
      U(    ;
      ON    "R-W Asse Z Foratrice".IMEF;
      O(    ;
      L     "R-W Asse Z Foratrice".QAttualeAsseZ;
      L     "Scambio dati OP".Q3AsseZForatrice;
      ==D   ;
      )     ;
      )     ;
      UN    "M68.1";
      UN    "M69.1";
      =     "M68.0";
NETWORK
TITLE =Asse Z Terzo Posizionamento Raggiunto

      U     "M60.1";
      U     "M68.0";
      U     "R-W Asse Z Foratrice".RLPDR;
      U(    ;
      L     "R-W Asse Z Foratrice".QAttualeAsseZ;
      L     "Scambio dati OP".Q3AsseZForatrice;
      ==D   ;
      )     ;
      S     "M68.1";
      U     "M69.1";
      R     "M68.1";
      NOP   0;
NETWORK
TITLE =Com Aut Start Terzo Posizionamento Asse Y

      U(    ;
      O     "M30.0";
      O     "M30.1";
      )     ;
      U     "M60.1";
      U     "M61.1";
      U     "EV104";
      U     "M12.7";
      U     "M67.6";
      U     "M68.1";
      U     "EV140";
      U(    ;
      UN    "Scambio dati OP".Pinza0_90Gradi3;
      U     "M11.6";
      O     ;
      U     "Scambio dati OP".Pinza0_90Gradi3;
      U     "M11.7";
      )     ;
      UN    "M68.4";
      UN    "M69.1";
      =     "M68.2";
NETWORK
TITLE =Asse Y in Movimento verso il Terzo Posizionamento

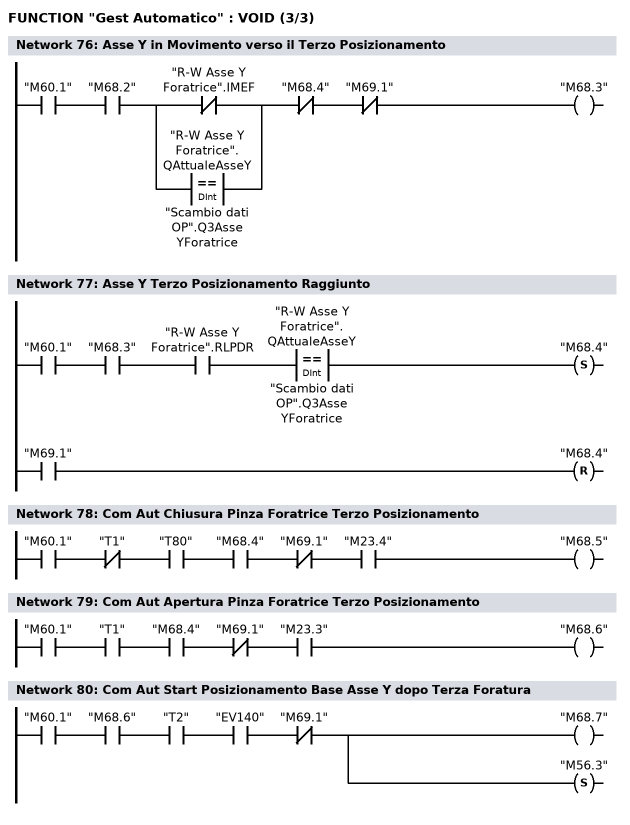
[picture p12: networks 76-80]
      U     "M60.1";
      U     "M68.2";
      U(    ;
      ON    "R-W Asse Y Foratrice".IMEF;
      O(    ;
      L     "R-W Asse Y Foratrice".QAttualeAsseY;
      L     "Scambio dati OP".Q3AsseYForatrice;
      ==D   ;
      )     ;
      )     ;
      UN    "M68.4";
      UN    "M69.1";
      =     "M68.3";
NETWORK
TITLE =Asse Y Terzo Posizionamento Raggiunto

      U     "M60.1";
      U     "M68.3";
      U     "R-W Asse Y Foratrice".RLPDR;
      U(    ;
      L     "R-W Asse Y Foratrice".QAttualeAsseY;
      L     "Scambio dati OP".Q3AsseYForatrice;
      ==D   ;
      )     ;
      S     "M68.4";
      U     "M69.1";
      R     "M68.4";
      NOP   0;
NETWORK
TITLE =Com Aut Chiusura Pinza Foratrice Terzo Posizionamento

      U     "M60.1";
      UN    "T1";
      U     "T80";
      U     "M68.4";
      UN    "M69.1";
      U     "M23.4";
      =     "M68.5";
NETWORK
TITLE =Com Aut Apertura Pinza Foratrice Terzo Posizionamento

      U     "M60.1";
      U     "T1";
      U     "M68.4";
      UN    "M69.1";
      U     "M23.3";
      =     "M68.6";
NETWORK
TITLE =Com Aut Start Posizionamento Base Asse Y dopo Terza Foratura

      U     "M60.1";
      U     "M68.6";
      U     "T2";
      U     "EV140";
      UN    "M69.1";
      =     "M68.7";
      S     "M56.3";
NETWORK
TITLE =

      U     "M56.3";
      =     L      0.0;
      U(    ;
      U     L      0.0;
      L     "Scambio dati OP".TempChiPinzaFor;
      SE    T     86;
      NOP   0;
      NOP   0;
      NOP   0;
      U     T     86;
      )     ;
      L     "Scambio dati OP".TempApePinzaFor;
      SE    T     87;
      NOP   0;
      NOP   0;
      NOP   0;
      NOP   0;
      U     L      0.0;
      UN    T     86;
      U     "M56.0";
      =     "M57.3";
      U     L      0.0;
      U     T     86;
      UN    T     87;
      U     "M56.0";
      =     "M58.3";
NETWORK
TITLE =Flag fine ciclo foratura 3

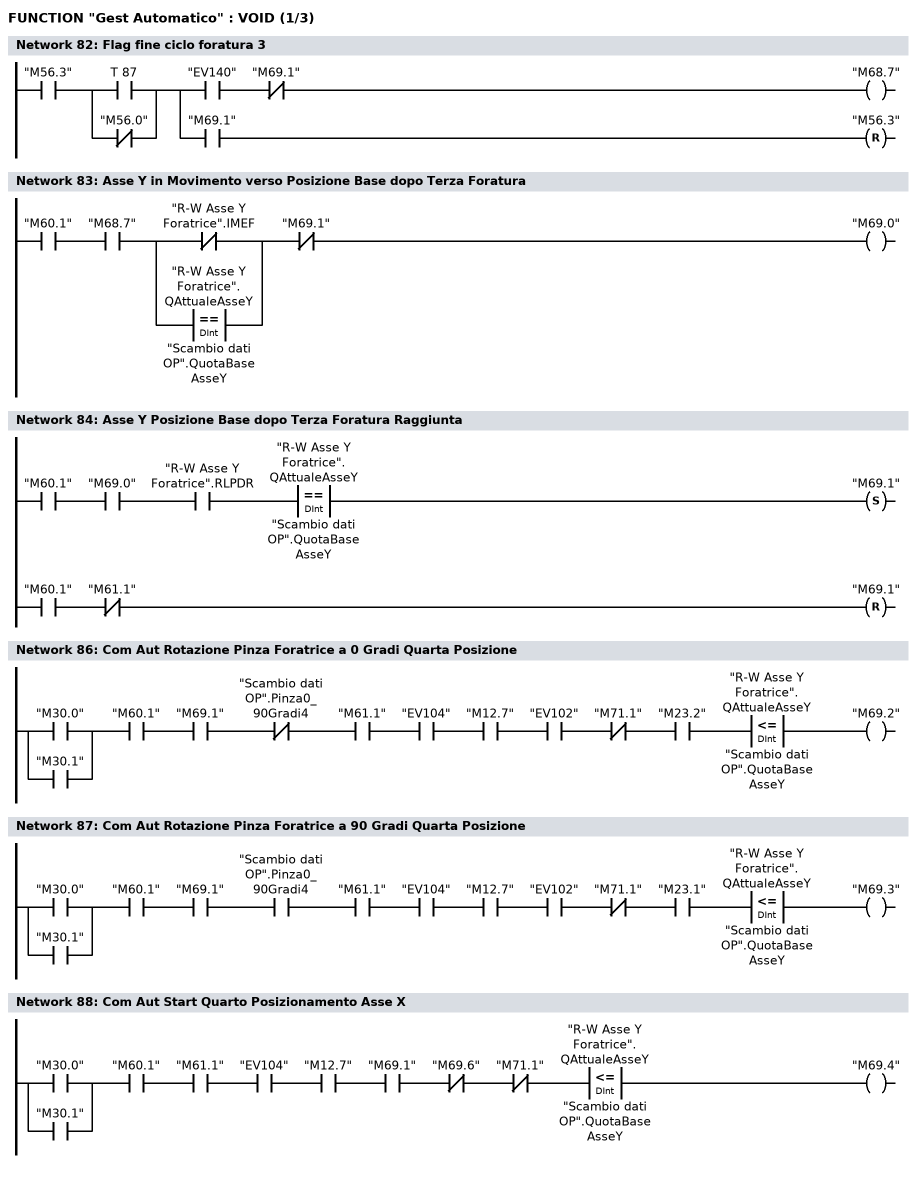
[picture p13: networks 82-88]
      U     "M56.3";
      U(    ;
      O     T     87;
      ON    "M56.0";
      )     ;
      =     L      0.0;
      U     L      0.0;
      U     "EV140";
      UN    "M69.1";
      =     "M68.7";
      U     L      0.0;
      U     "M69.1";
      R     "M56.3";
NETWORK
TITLE =Asse Y in Movimento verso Posizione Base dopo Terza Foratura

      U     "M60.1";
      U     "M68.7";
      U(    ;
      ON    "R-W Asse Y Foratrice".IMEF;
      O(    ;
      L     "R-W Asse Y Foratrice".QAttualeAsseY;
      L     "Scambio dati OP".QuotaBaseAsseY;
      ==D   ;
      )     ;
      )     ;
      UN    "M69.1";
      =     "M69.0";
NETWORK
TITLE =Asse Y Posizione Base dopo Terza Foratura Raggiunta

      U     "M60.1";
      U     "M69.0";
      U     "R-W Asse Y Foratrice".RLPDR;
      U(    ;
      L     "R-W Asse Y Foratrice".QAttualeAsseY;
      L     "Scambio dati OP".QuotaBaseAsseY;
      ==D   ;
      )     ;
      S     "M69.1";
      U     "M60.1";
      UN    "M61.1";
      R     "M69.1";
      NOP   0;
NETWORK
TITLE ======== Quarto Posizionamento Foratrice =======



NETWORK
TITLE =Com Aut Rotazione Pinza Foratrice a 0 Gradi Quarta Posizione

      U(    ;
      O     "M30.0";
      O     "M30.1";
      )     ;
      U     "M60.1";
      U     "M69.1";
      UN    "Scambio dati OP".Pinza0_90Gradi4;
      U     "M61.1";
      U     "EV104";
      U     "M12.7";
      U     "EV102";
      UN    "M71.1";
      U     "M23.2";
      U(    ;
      L     "R-W Asse Y Foratrice".QAttualeAsseY;
      L     "Scambio dati OP".QuotaBaseAsseY;
      <=D   ;
      )     ;
      =     "M69.2";
NETWORK
TITLE =Com Aut Rotazione Pinza Foratrice a 90 Gradi Quarta Posizione

      U(    ;
      O     "M30.0";
      O     "M30.1";
      )     ;
      U     "M60.1";
      U     "M69.1";
      U     "Scambio dati OP".Pinza0_90Gradi4;
      U     "M61.1";
      U     "EV104";
      U     "M12.7";
      U     "EV102";
      UN    "M71.1";
      U     "M23.1";
      U(    ;
      L     "R-W Asse Y Foratrice".QAttualeAsseY;
      L     "Scambio dati OP".QuotaBaseAsseY;
      <=D   ;
      )     ;
      =     "M69.3";
NETWORK
TITLE =Com Aut Start Quarto Posizionamento Asse X

      U(    ;
      O     "M30.0";
      O     "M30.1";
      )     ;
      U     "M60.1";
      U     "M61.1";
      U     "EV104";
      U     "M12.7";
      U     "M69.1";
      UN    "M69.6";
      UN    "M71.1";
      U(    ;
      L     "R-W Asse Y Foratrice".QAttualeAsseY;
      L     "Scambio dati OP".QuotaBaseAsseY;
      <=D   ;
      )     ;
      =     "M69.4";
NETWORK
TITLE =Asse X in Movimento verso il Quarto Posizionamento

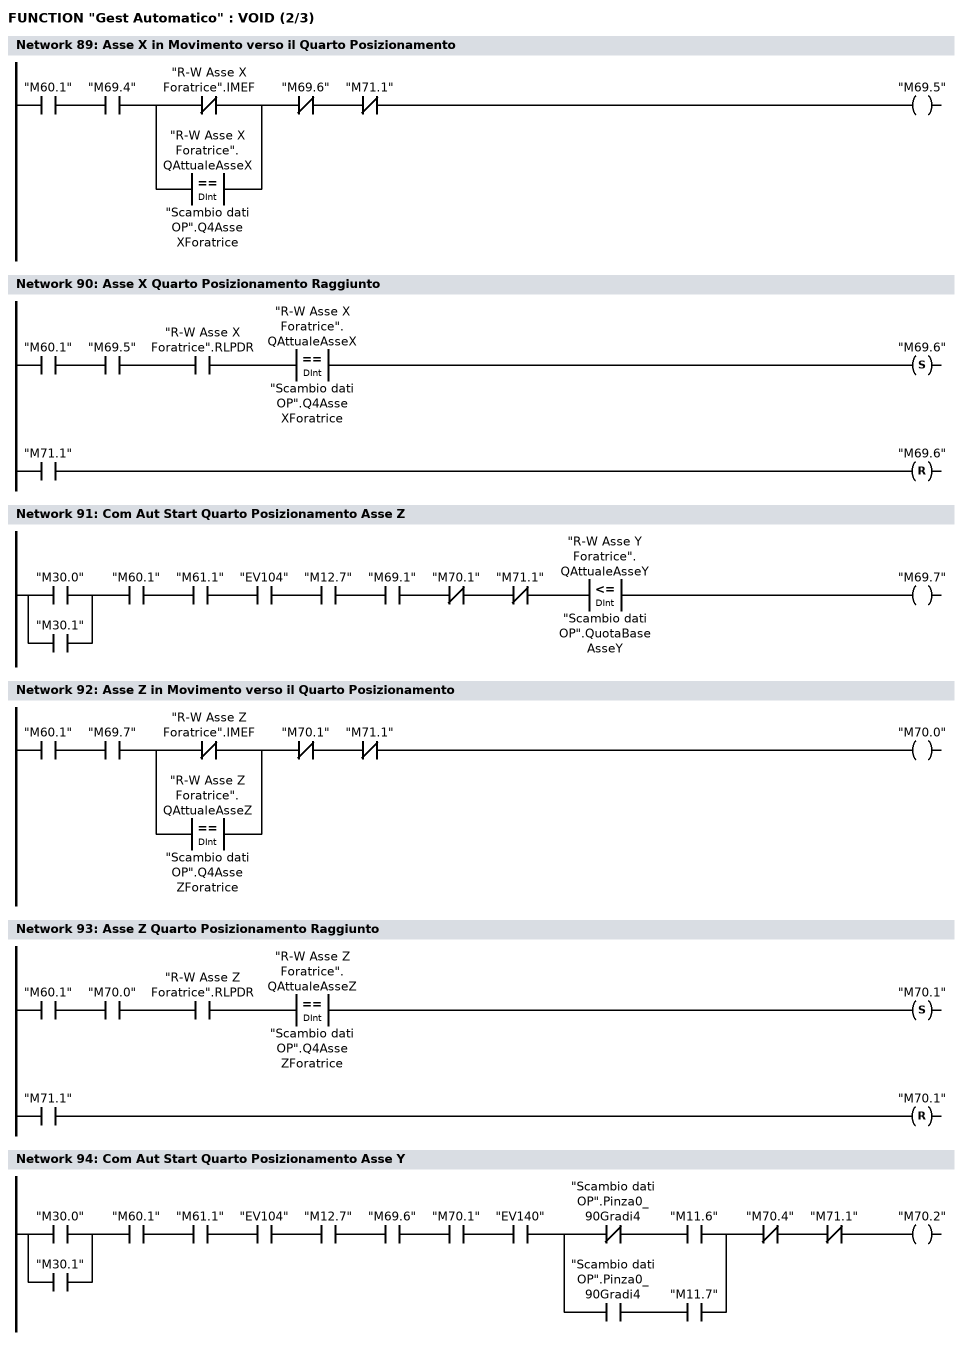
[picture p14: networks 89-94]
      U     "M60.1";
      U     "M69.4";
      U(    ;
      ON    "R-W Asse X Foratrice".IMEF;
      O(    ;
      L     "R-W Asse X Foratrice".QAttualeAsseX;
      L     "Scambio dati OP".Q4AsseXForatrice;
      ==D   ;
      )     ;
      )     ;
      UN    "M69.6";
      UN    "M71.1";
      =     "M69.5";
NETWORK
TITLE =Asse X Quarto Posizionamento Raggiunto

      U     "M60.1";
      U     "M69.5";
      U     "R-W Asse X Foratrice".RLPDR;
      U(    ;
      L     "R-W Asse X Foratrice".QAttualeAsseX;
      L     "Scambio dati OP".Q4AsseXForatrice;
      ==D   ;
      )     ;
      S     "M69.6";
      U     "M71.1";
      R     "M69.6";
      NOP   0;
NETWORK
TITLE =Com Aut Start Quarto Posizionamento Asse Z

      U(    ;
      O     "M30.0";
      O     "M30.1";
      )     ;
      U     "M60.1";
      U     "M61.1";
      U     "EV104";
      U     "M12.7";
      U     "M69.1";
      UN    "M70.1";
      UN    "M71.1";
      U(    ;
      L     "R-W Asse Y Foratrice".QAttualeAsseY;
      L     "Scambio dati OP".QuotaBaseAsseY;
      <=D   ;
      )     ;
      =     "M69.7";
NETWORK
TITLE =Asse Z in Movimento verso il Quarto Posizionamento

      U     "M60.1";
      U     "M69.7";
      U(    ;
      ON    "R-W Asse Z Foratrice".IMEF;
      O(    ;
      L     "R-W Asse Z Foratrice".QAttualeAsseZ;
      L     "Scambio dati OP".Q4AsseZForatrice;
      ==D   ;
      )     ;
      )     ;
      UN    "M70.1";
      UN    "M71.1";
      =     "M70.0";
NETWORK
TITLE =Asse Z Quarto Posizionamento Raggiunto

      U     "M60.1";
      U     "M70.0";
      U     "R-W Asse Z Foratrice".RLPDR;
      U(    ;
      L     "R-W Asse Z Foratrice".QAttualeAsseZ;
      L     "Scambio dati OP".Q4AsseZForatrice;
      ==D   ;
      )     ;
      S     "M70.1";
      U     "M71.1";
      R     "M70.1";
      NOP   0;
NETWORK
TITLE =Com Aut Start Quarto Posizionamento Asse Y

      U(    ;
      O     "M30.0";
      O     "M30.1";
      )     ;
      U     "M60.1";
      U     "M61.1";
      U     "EV104";
      U     "M12.7";
      U     "M69.6";
      U     "M70.1";
      U     "EV140";
      U(    ;
      UN    "Scambio dati OP".Pinza0_90Gradi4;
      U     "M11.6";
      O     ;
      U     "Scambio dati OP".Pinza0_90Gradi4;
      U     "M11.7";
      )     ;
      UN    "M70.4";
      UN    "M71.1";
      =     "M70.2";
NETWORK
TITLE =Asse Y in Movimento verso il Quarto Posizionamento

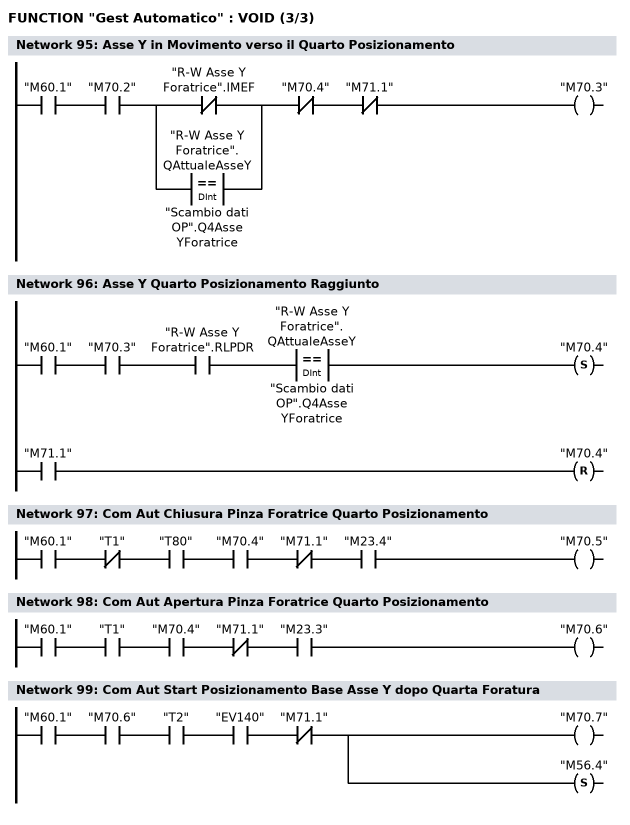
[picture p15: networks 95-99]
      U     "M60.1";
      U     "M70.2";
      U(    ;
      ON    "R-W Asse Y Foratrice".IMEF;
      O(    ;
      L     "R-W Asse Y Foratrice".QAttualeAsseY;
      L     "Scambio dati OP".Q4AsseYForatrice;
      ==D   ;
      )     ;
      )     ;
      UN    "M70.4";
      UN    "M71.1";
      =     "M70.3";
NETWORK
TITLE =Asse Y Quarto Posizionamento Raggiunto

      U     "M60.1";
      U     "M70.3";
      U     "R-W Asse Y Foratrice".RLPDR;
      U(    ;
      L     "R-W Asse Y Foratrice".QAttualeAsseY;
      L     "Scambio dati OP".Q4AsseYForatrice;
      ==D   ;
      )     ;
      S     "M70.4";
      U     "M71.1";
      R     "M70.4";
      NOP   0;
NETWORK
TITLE =Com Aut Chiusura Pinza Foratrice Quarto Posizionamento

      U     "M60.1";
      UN    "T1";
      U     "T80";
      U     "M70.4";
      UN    "M71.1";
      U     "M23.4";
      =     "M70.5";
NETWORK
TITLE =Com Aut Apertura Pinza Foratrice Quarto Posizionamento

      U     "M60.1";
      U     "T1";
      U     "M70.4";
      UN    "M71.1";
      U     "M23.3";
      =     "M70.6";
NETWORK
TITLE =Com Aut Start Posizionamento Base Asse Y dopo Quarta Foratura

      U     "M60.1";
      U     "M70.6";
      U     "T2";
      U     "EV140";
      UN    "M71.1";
      =     "M70.7";
      S     "M56.4";
NETWORK
TITLE =

      U     "M56.4";
      =     L      0.0;
      U(    ;
      U     L      0.0;
      L     "Scambio dati OP".TempChiPinzaFor;
      SE    T     88;
      NOP   0;
      NOP   0;
      NOP   0;
      U     T     88;
      )     ;
      L     "Scambio dati OP".TempApePinzaFor;
      SE    T     89;
      NOP   0;
      NOP   0;
      NOP   0;
      NOP   0;
      U     L      0.0;
      UN    T     88;
      U     "M56.0";
      =     "M57.4";
      U     L      0.0;
      U     T     88;
      UN    T     89;
      U     "M56.0";
      =     "M58.4";
NETWORK
TITLE =Flag fine ciclo foratura 4

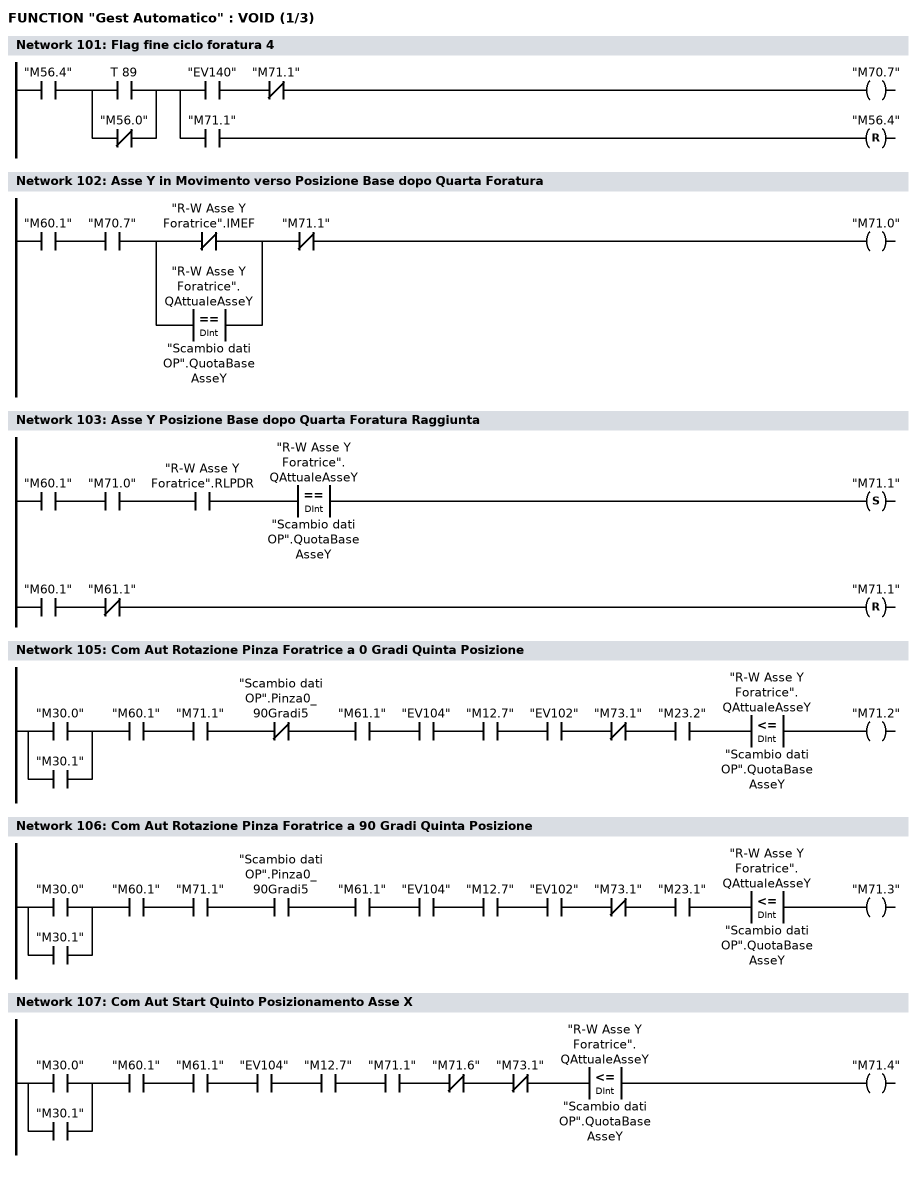
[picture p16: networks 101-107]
      U     "M56.4";
      U(    ;
      O     T     89;
      ON    "M56.0";
      )     ;
      =     L      0.0;
      U     L      0.0;
      U     "EV140";
      UN    "M71.1";
      =     "M70.7";
      U     L      0.0;
      U     "M71.1";
      R     "M56.4";
NETWORK
TITLE =Asse Y in Movimento verso Posizione Base dopo Quarta Foratura

      U     "M60.1";
      U     "M70.7";
      U(    ;
      ON    "R-W Asse Y Foratrice".IMEF;
      O(    ;
      L     "R-W Asse Y Foratrice".QAttualeAsseY;
      L     "Scambio dati OP".QuotaBaseAsseY;
      ==D   ;
      )     ;
      )     ;
      UN    "M71.1";
      =     "M71.0";
NETWORK
TITLE =Asse Y Posizione Base dopo Quarta Foratura Raggiunta

      U     "M60.1";
      U     "M71.0";
      U     "R-W Asse Y Foratrice".RLPDR;
      U(    ;
      L     "R-W Asse Y Foratrice".QAttualeAsseY;
      L     "Scambio dati OP".QuotaBaseAsseY;
      ==D   ;
      )     ;
      S     "M71.1";
      U     "M60.1";
      UN    "M61.1";
      R     "M71.1";
      NOP   0;
NETWORK
TITLE ======== Quinto Posizionamento Foratrice =======



NETWORK
TITLE =Com Aut Rotazione Pinza Foratrice a 0 Gradi Quinta Posizione

      U(    ;
      O     "M30.0";
      O     "M30.1";
      )     ;
      U     "M60.1";
      U     "M71.1";
      UN    "Scambio dati OP".Pinza0_90Gradi5;
      U     "M61.1";
      U     "EV104";
      U     "M12.7";
      U     "EV102";
      UN    "M73.1";
      U     "M23.2";
      U(    ;
      L     "R-W Asse Y Foratrice".QAttualeAsseY;
      L     "Scambio dati OP".QuotaBaseAsseY;
      <=D   ;
      )     ;
      =     "M71.2";
NETWORK
TITLE =Com Aut Rotazione Pinza Foratrice a 90 Gradi Quinta Posizione

      U(    ;
      O     "M30.0";
      O     "M30.1";
      )     ;
      U     "M60.1";
      U     "M71.1";
      U     "Scambio dati OP".Pinza0_90Gradi5;
      U     "M61.1";
      U     "EV104";
      U     "M12.7";
      U     "EV102";
      UN    "M73.1";
      U     "M23.1";
      U(    ;
      L     "R-W Asse Y Foratrice".QAttualeAsseY;
      L     "Scambio dati OP".QuotaBaseAsseY;
      <=D   ;
      )     ;
      =     "M71.3";
NETWORK
TITLE =Com Aut Start Quinto Posizionamento Asse X

      U(    ;
      O     "M30.0";
      O     "M30.1";
      )     ;
      U     "M60.1";
      U     "M61.1";
      U     "EV104";
      U     "M12.7";
      U     "M71.1";
      UN    "M71.6";
      UN    "M73.1";
      U(    ;
      L     "R-W Asse Y Foratrice".QAttualeAsseY;
      L     "Scambio dati OP".QuotaBaseAsseY;
      <=D   ;
      )     ;
      =     "M71.4";
NETWORK
TITLE =Asse X in Movimento verso il Quinto Posizionamento

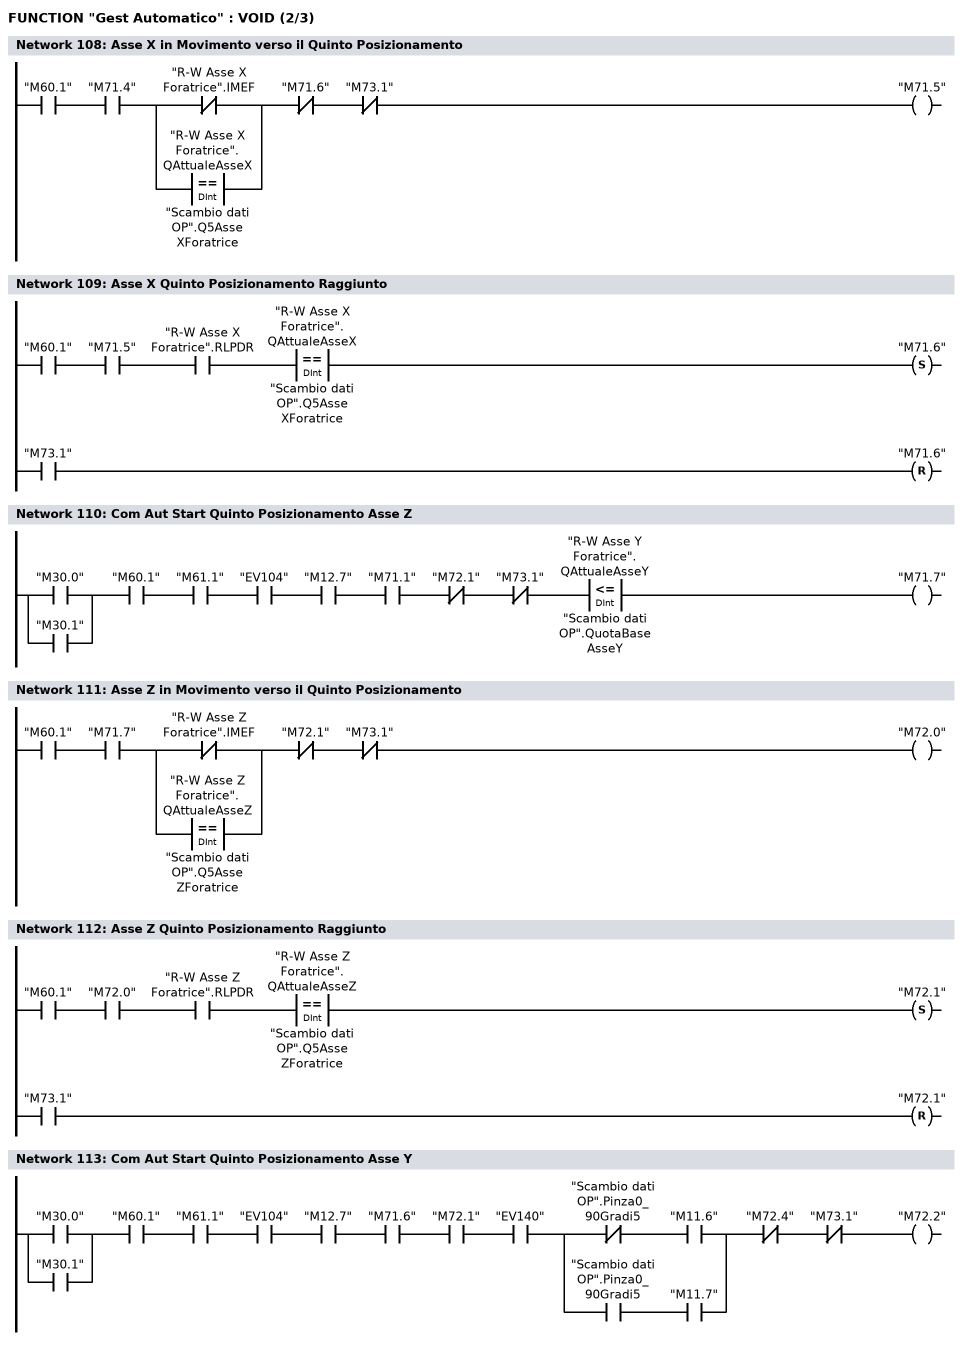
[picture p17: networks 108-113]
      U     "M60.1";
      U     "M71.4";
      U(    ;
      ON    "R-W Asse X Foratrice".IMEF;
      O(    ;
      L     "R-W Asse X Foratrice".QAttualeAsseX;
      L     "Scambio dati OP".Q5AsseXForatrice;
      ==D   ;
      )     ;
      )     ;
      UN    "M71.6";
      UN    "M73.1";
      =     "M71.5";
NETWORK
TITLE =Asse X Quinto Posizionamento Raggiunto

      U     "M60.1";
      U     "M71.5";
      U     "R-W Asse X Foratrice".RLPDR;
      U(    ;
      L     "R-W Asse X Foratrice".QAttualeAsseX;
      L     "Scambio dati OP".Q5AsseXForatrice;
      ==D   ;
      )     ;
      S     "M71.6";
      U     "M73.1";
      R     "M71.6";
      NOP   0;
NETWORK
TITLE =Com Aut Start Quinto Posizionamento Asse Z

      U(    ;
      O     "M30.0";
      O     "M30.1";
      )     ;
      U     "M60.1";
      U     "M61.1";
      U     "EV104";
      U     "M12.7";
      U     "M71.1";
      UN    "M72.1";
      UN    "M73.1";
      U(    ;
      L     "R-W Asse Y Foratrice".QAttualeAsseY;
      L     "Scambio dati OP".QuotaBaseAsseY;
      <=D   ;
      )     ;
      =     "M71.7";
NETWORK
TITLE =Asse Z in Movimento verso il Quinto Posizionamento

      U     "M60.1";
      U     "M71.7";
      U(    ;
      ON    "R-W Asse Z Foratrice".IMEF;
      O(    ;
      L     "R-W Asse Z Foratrice".QAttualeAsseZ;
      L     "Scambio dati OP".Q5AsseZForatrice;
      ==D   ;
      )     ;
      )     ;
      UN    "M72.1";
      UN    "M73.1";
      =     "M72.0";
NETWORK
TITLE =Asse Z Quinto Posizionamento Raggiunto

      U     "M60.1";
      U     "M72.0";
      U     "R-W Asse Z Foratrice".RLPDR;
      U(    ;
      L     "R-W Asse Z Foratrice".QAttualeAsseZ;
      L     "Scambio dati OP".Q5AsseZForatrice;
      ==D   ;
      )     ;
      S     "M72.1";
      U     "M73.1";
      R     "M72.1";
      NOP   0;
NETWORK
TITLE =Com Aut Start Quinto Posizionamento Asse Y

      U(    ;
      O     "M30.0";
      O     "M30.1";
      )     ;
      U     "M60.1";
      U     "M61.1";
      U     "EV104";
      U     "M12.7";
      U     "M71.6";
      U     "M72.1";
      U     "EV140";
      U(    ;
      UN    "Scambio dati OP".Pinza0_90Gradi5;
      U     "M11.6";
      O     ;
      U     "Scambio dati OP".Pinza0_90Gradi5;
      U     "M11.7";
      )     ;
      UN    "M72.4";
      UN    "M73.1";
      =     "M72.2";
NETWORK
TITLE =Asse Y in Movimento verso il Quinto Posizionamento

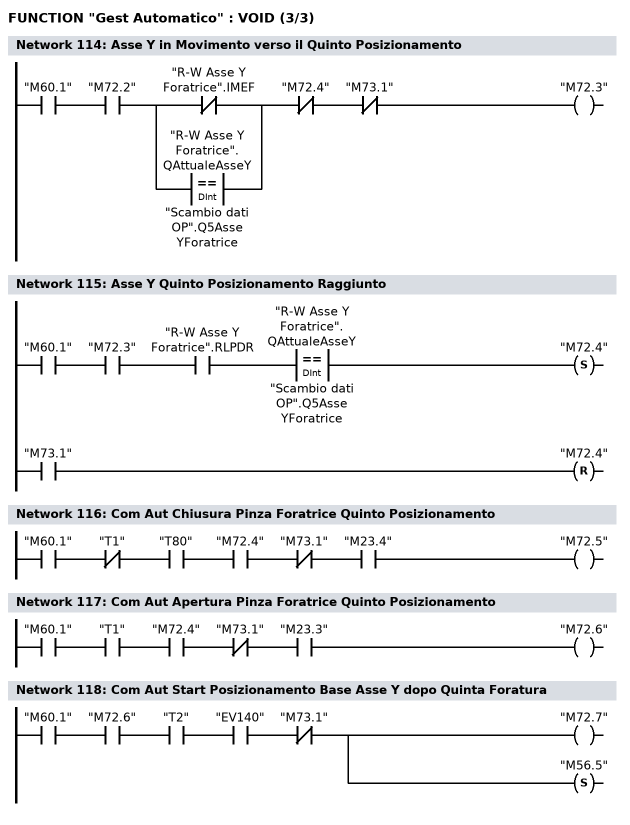
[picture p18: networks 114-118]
      U     "M60.1";
      U     "M72.2";
      U(    ;
      ON    "R-W Asse Y Foratrice".IMEF;
      O(    ;
      L     "R-W Asse Y Foratrice".QAttualeAsseY;
      L     "Scambio dati OP".Q5AsseYForatrice;
      ==D   ;
      )     ;
      )     ;
      UN    "M72.4";
      UN    "M73.1";
      =     "M72.3";
NETWORK
TITLE =Asse Y Quinto Posizionamento Raggiunto

      U     "M60.1";
      U     "M72.3";
      U     "R-W Asse Y Foratrice".RLPDR;
      U(    ;
      L     "R-W Asse Y Foratrice".QAttualeAsseY;
      L     "Scambio dati OP".Q5AsseYForatrice;
      ==D   ;
      )     ;
      S     "M72.4";
      U     "M73.1";
      R     "M72.4";
      NOP   0;
NETWORK
TITLE =Com Aut Chiusura Pinza Foratrice Quinto Posizionamento

      U     "M60.1";
      UN    "T1";
      U     "T80";
      U     "M72.4";
      UN    "M73.1";
      U     "M23.4";
      =     "M72.5";
NETWORK
TITLE =Com Aut Apertura Pinza Foratrice Quinto Posizionamento

      U     "M60.1";
      U     "T1";
      U     "M72.4";
      UN    "M73.1";
      U     "M23.3";
      =     "M72.6";
NETWORK
TITLE =Com Aut Start Posizionamento Base Asse Y dopo Quinta Foratura

      U     "M60.1";
      U     "M72.6";
      U     "T2";
      U     "EV140";
      UN    "M73.1";
      =     "M72.7";
      S     "M56.5";
NETWORK
TITLE =

      U     "M56.5";
      =     L      0.0;
      U(    ;
      U     L      0.0;
      L     "Scambio dati OP".TempChiPinzaFor;
      SE    T     18;
      NOP   0;
      NOP   0;
      NOP   0;
      U     T     18;
      )     ;
      L     "Scambio dati OP".TempApePinzaFor;
      SE    T     19;
      NOP   0;
      NOP   0;
      NOP   0;
      NOP   0;
      U     L      0.0;
      UN    T     18;
      U     "M56.0";
      =     "M57.5";
      U     L      0.0;
      U     T     18;
      UN    T     19;
      U     "M56.0";
      =     "M58.5";
NETWORK
TITLE =Flag fine ciclo foratura 5

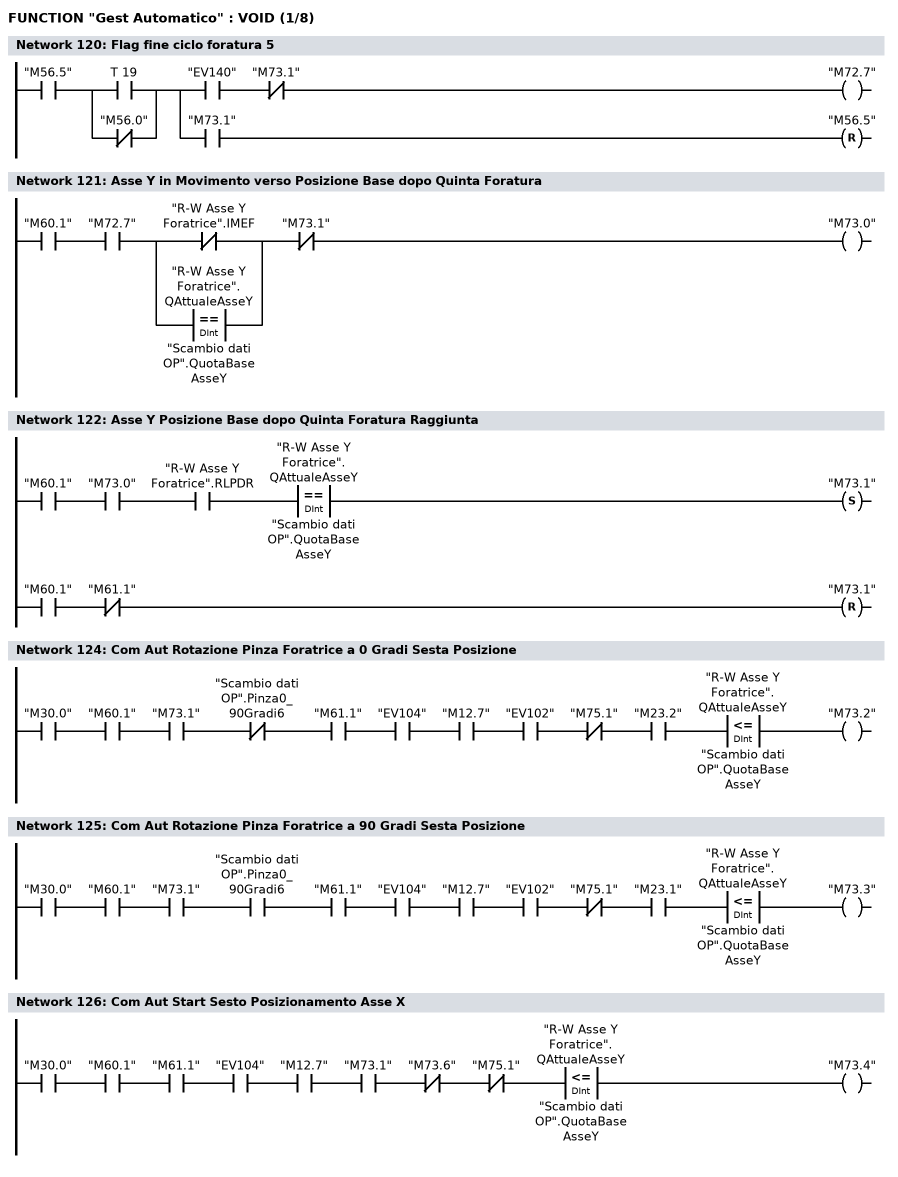
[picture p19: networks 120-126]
      U     "M56.5";
      U(    ;
      O     T     19;
      ON    "M56.0";
      )     ;
      =     L      0.0;
      U     L      0.0;
      U     "EV140";
      UN    "M73.1";
      =     "M72.7";
      U     L      0.0;
      U     "M73.1";
      R     "M56.5";
NETWORK
TITLE =Asse Y in Movimento verso Posizione Base dopo Quinta Foratura

      U     "M60.1";
      U     "M72.7";
      U(    ;
      ON    "R-W Asse Y Foratrice".IMEF;
      O(    ;
      L     "R-W Asse Y Foratrice".QAttualeAsseY;
      L     "Scambio dati OP".QuotaBaseAsseY;
      ==D   ;
      )     ;
      )     ;
      UN    "M73.1";
      =     "M73.0";
NETWORK
TITLE =Asse Y Posizione Base dopo Quinta Foratura Raggiunta

      U     "M60.1";
      U     "M73.0";
      U     "R-W Asse Y Foratrice".RLPDR;
      U(    ;
      L     "R-W Asse Y Foratrice".QAttualeAsseY;
      L     "Scambio dati OP".QuotaBaseAsseY;
      ==D   ;
      )     ;
      S     "M73.1";
      U     "M60.1";
      UN    "M61.1";
      R     "M73.1";
      NOP   0;
NETWORK
TITLE ======== Sesto Posizionamento Foratrice =======



NETWORK
TITLE =Com Aut Rotazione Pinza Foratrice a 0 Gradi Sesta Posizione

      U     "M30.0";
      U     "M60.1";
      U     "M73.1";
      UN    "Scambio dati OP".Pinza0_90Gradi6;
      U     "M61.1";
      U     "EV104";
      U     "M12.7";
      U     "EV102";
      UN    "M75.1";
      U     "M23.2";
      U(    ;
      L     "R-W Asse Y Foratrice".QAttualeAsseY;
      L     "Scambio dati OP".QuotaBaseAsseY;
      <=D   ;
      )     ;
      =     "M73.2";
NETWORK
TITLE =Com Aut Rotazione Pinza Foratrice a 90 Gradi Sesta Posizione

      U     "M30.0";
      U     "M60.1";
      U     "M73.1";
      U     "Scambio dati OP".Pinza0_90Gradi6;
      U     "M61.1";
      U     "EV104";
      U     "M12.7";
      U     "EV102";
      UN    "M75.1";
      U     "M23.1";
      U(    ;
      L     "R-W Asse Y Foratrice".QAttualeAsseY;
      L     "Scambio dati OP".QuotaBaseAsseY;
      <=D   ;
      )     ;
      =     "M73.3";
NETWORK
TITLE =Com Aut Start Sesto Posizionamento Asse X

      U     "M30.0";
      U     "M60.1";
      U     "M61.1";
      U     "EV104";
      U     "M12.7";
      U     "M73.1";
      UN    "M73.6";
      UN    "M75.1";
      U(    ;
      L     "R-W Asse Y Foratrice".QAttualeAsseY;
      L     "Scambio dati OP".QuotaBaseAsseY;
      <=D   ;
      )     ;
      =     "M73.4";
NETWORK
TITLE =Asse X in Movimento verso il Sesto Posizionamento

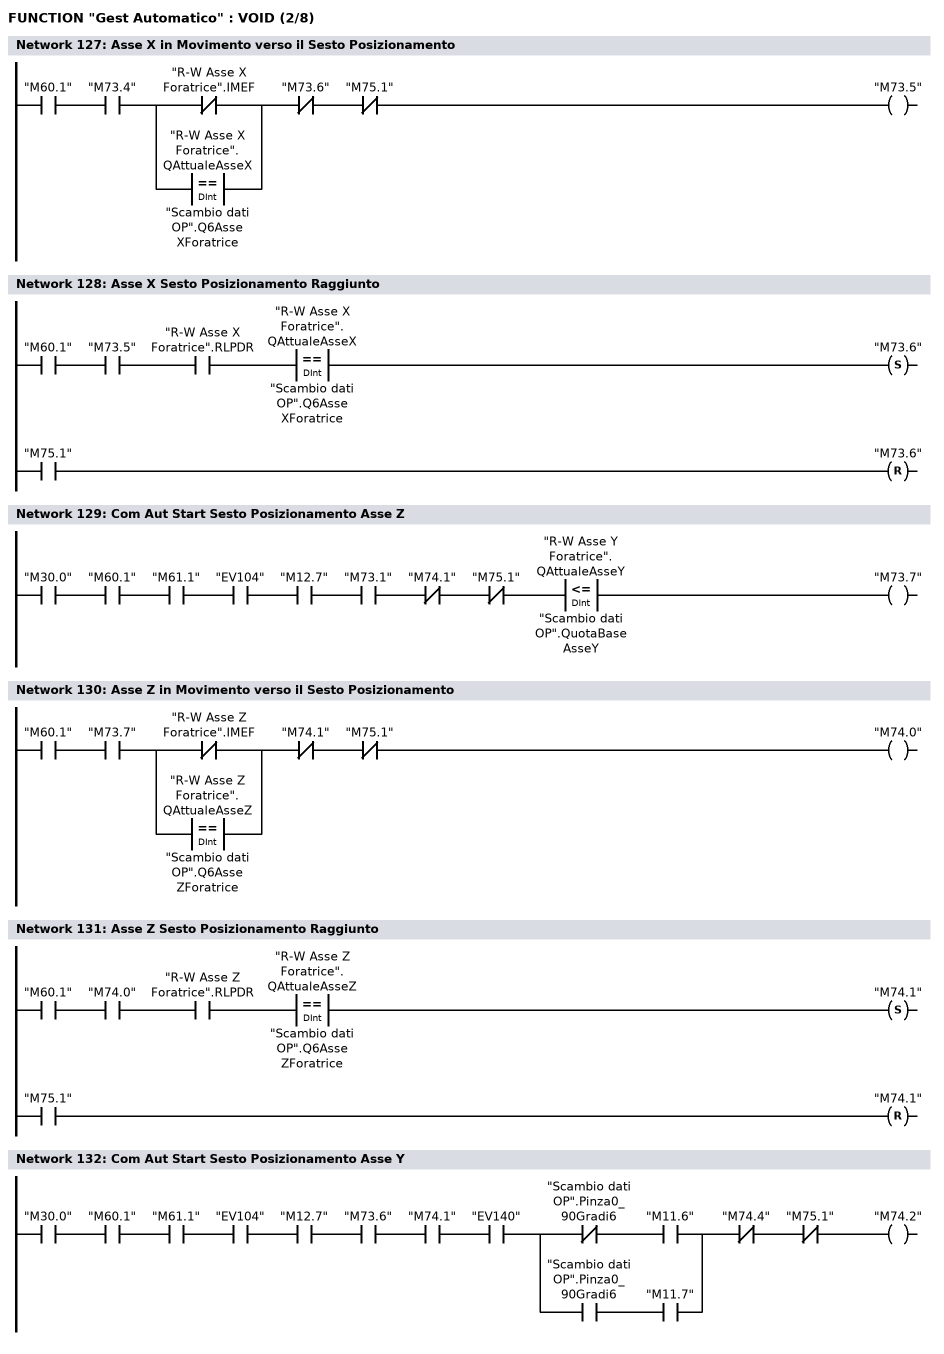
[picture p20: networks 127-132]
      U     "M60.1";
      U     "M73.4";
      U(    ;
      ON    "R-W Asse X Foratrice".IMEF;
      O(    ;
      L     "R-W Asse X Foratrice".QAttualeAsseX;
      L     "Scambio dati OP".Q6AsseXForatrice;
      ==D   ;
      )     ;
      )     ;
      UN    "M73.6";
      UN    "M75.1";
      =     "M73.5";
NETWORK
TITLE =Asse X Sesto Posizionamento Raggiunto

      U     "M60.1";
      U     "M73.5";
      U     "R-W Asse X Foratrice".RLPDR;
      U(    ;
      L     "R-W Asse X Foratrice".QAttualeAsseX;
      L     "Scambio dati OP".Q6AsseXForatrice;
      ==D   ;
      )     ;
      S     "M73.6";
      U     "M75.1";
      R     "M73.6";
      NOP   0;
NETWORK
TITLE =Com Aut Start Sesto Posizionamento Asse Z

      U     "M30.0";
      U     "M60.1";
      U     "M61.1";
      U     "EV104";
      U     "M12.7";
      U     "M73.1";
      UN    "M74.1";
      UN    "M75.1";
      U(    ;
      L     "R-W Asse Y Foratrice".QAttualeAsseY;
      L     "Scambio dati OP".QuotaBaseAsseY;
      <=D   ;
      )     ;
      =     "M73.7";
NETWORK
TITLE =Asse Z in Movimento verso il Sesto Posizionamento

      U     "M60.1";
      U     "M73.7";
      U(    ;
      ON    "R-W Asse Z Foratrice".IMEF;
      O(    ;
      L     "R-W Asse Z Foratrice".QAttualeAsseZ;
      L     "Scambio dati OP".Q6AsseZForatrice;
      ==D   ;
      )     ;
      )     ;
      UN    "M74.1";
      UN    "M75.1";
      =     "M74.0";
NETWORK
TITLE =Asse Z Sesto Posizionamento Raggiunto

      U     "M60.1";
      U     "M74.0";
      U     "R-W Asse Z Foratrice".RLPDR;
      U(    ;
      L     "R-W Asse Z Foratrice".QAttualeAsseZ;
      L     "Scambio dati OP".Q6AsseZForatrice;
      ==D   ;
      )     ;
      S     "M74.1";
      U     "M75.1";
      R     "M74.1";
      NOP   0;
NETWORK
TITLE =Com Aut Start Sesto Posizionamento Asse Y

      U     "M30.0";
      U     "M60.1";
      U     "M61.1";
      U     "EV104";
      U     "M12.7";
      U     "M73.6";
      U     "M74.1";
      U     "EV140";
      U(    ;
      UN    "Scambio dati OP".Pinza0_90Gradi6;
      U     "M11.6";
      O     ;
      U     "Scambio dati OP".Pinza0_90Gradi6;
      U     "M11.7";
      )     ;
      UN    "M74.4";
      UN    "M75.1";
      =     "M74.2";
NETWORK
TITLE =Asse Y in Movimento verso il Sesto Posizionamento

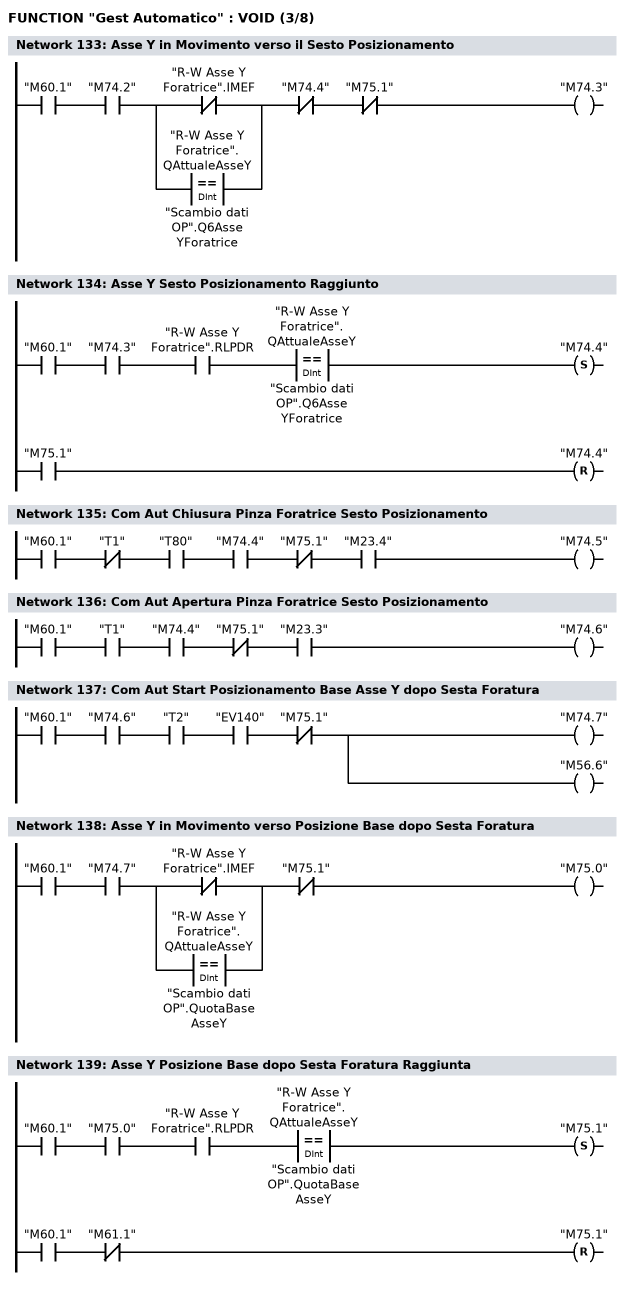
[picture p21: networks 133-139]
      U     "M60.1";
      U     "M74.2";
      U(    ;
      ON    "R-W Asse Y Foratrice".IMEF;
      O(    ;
      L     "R-W Asse Y Foratrice".QAttualeAsseY;
      L     "Scambio dati OP".Q6AsseYForatrice;
      ==D   ;
      )     ;
      )     ;
      UN    "M74.4";
      UN    "M75.1";
      =     "M74.3";
NETWORK
TITLE =Asse Y Sesto Posizionamento Raggiunto

      U     "M60.1";
      U     "M74.3";
      U     "R-W Asse Y Foratrice".RLPDR;
      U(    ;
      L     "R-W Asse Y Foratrice".QAttualeAsseY;
      L     "Scambio dati OP".Q6AsseYForatrice;
      ==D   ;
      )     ;
      S     "M74.4";
      U     "M75.1";
      R     "M74.4";
      NOP   0;
NETWORK
TITLE =Com Aut Chiusura Pinza Foratrice Sesto Posizionamento

      U     "M60.1";
      UN    "T1";
      U     "T80";
      U     "M74.4";
      UN    "M75.1";
      U     "M23.4";
      =     "M74.5";
NETWORK
TITLE =Com Aut Apertura Pinza Foratrice Sesto Posizionamento

      U     "M60.1";
      U     "T1";
      U     "M74.4";
      UN    "M75.1";
      U     "M23.3";
      =     "M74.6";
NETWORK
TITLE =Com Aut Start Posizionamento Base Asse Y dopo Sesta Foratura

      U     "M60.1";
      U     "M74.6";
      U     "T2";
      U     "EV140";
      UN    "M75.1";
      =     "M74.7";
      =     "M56.6";
NETWORK
TITLE =Asse Y in Movimento verso Posizione Base dopo Sesta Foratura

      U     "M60.1";
      U     "M74.7";
      U(    ;
      ON    "R-W Asse Y Foratrice".IMEF;
      O(    ;
      L     "R-W Asse Y Foratrice".QAttualeAsseY;
      L     "Scambio dati OP".QuotaBaseAsseY;
      ==D   ;
      )     ;
      )     ;
      UN    "M75.1";
      =     "M75.0";
NETWORK
TITLE =Asse Y Posizione Base dopo Sesta Foratura Raggiunta

      U     "M60.1";
      U     "M75.0";
      U     "R-W Asse Y Foratrice".RLPDR;
      U(    ;
      L     "R-W Asse Y Foratrice".QAttualeAsseY;
      L     "Scambio dati OP".QuotaBaseAsseY;
      ==D   ;
      )     ;
      S     "M75.1";
      U     "M60.1";
      UN    "M61.1";
      R     "M75.1";
      NOP   0;
NETWORK
TITLE ======== Settimo Posizionamento Foratrice =======



NETWORK
TITLE =Com Aut Rotazione Pinza Foratrice a 0 Gradi Settima Posizione

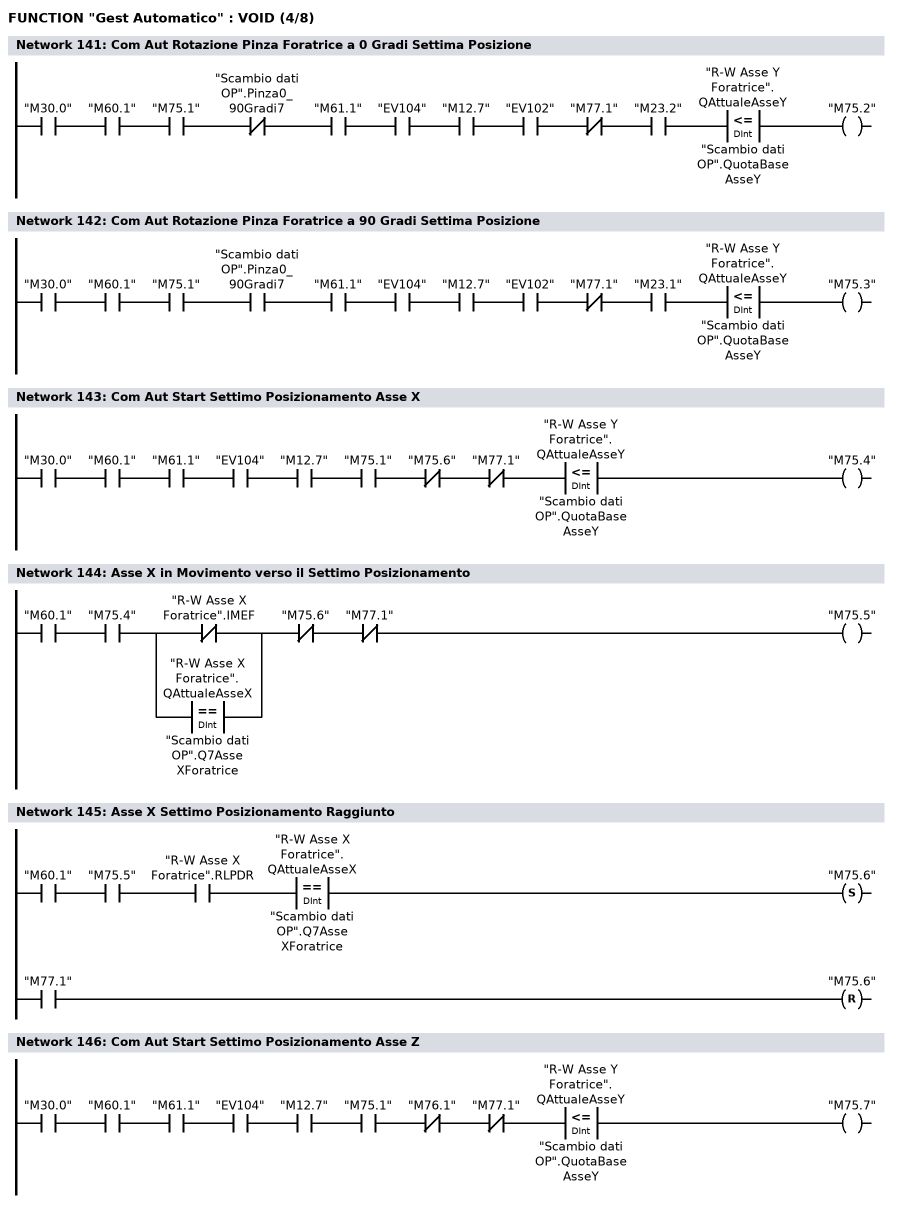
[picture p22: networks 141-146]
      U     "M30.0";
      U     "M60.1";
      U     "M75.1";
      UN    "Scambio dati OP".Pinza0_90Gradi7;
      U     "M61.1";
      U     "EV104";
      U     "M12.7";
      U     "EV102";
      UN    "M77.1";
      U     "M23.2";
      U(    ;
      L     "R-W Asse Y Foratrice".QAttualeAsseY;
      L     "Scambio dati OP".QuotaBaseAsseY;
      <=D   ;
      )     ;
      =     "M75.2";
NETWORK
TITLE =Com Aut Rotazione Pinza Foratrice a 90 Gradi Settima Posizione

      U     "M30.0";
      U     "M60.1";
      U     "M75.1";
      U     "Scambio dati OP".Pinza0_90Gradi7;
      U     "M61.1";
      U     "EV104";
      U     "M12.7";
      U     "EV102";
      UN    "M77.1";
      U     "M23.1";
      U(    ;
      L     "R-W Asse Y Foratrice".QAttualeAsseY;
      L     "Scambio dati OP".QuotaBaseAsseY;
      <=D   ;
      )     ;
      =     "M75.3";
NETWORK
TITLE =Com Aut Start Settimo Posizionamento Asse X

      U     "M30.0";
      U     "M60.1";
      U     "M61.1";
      U     "EV104";
      U     "M12.7";
      U     "M75.1";
      UN    "M75.6";
      UN    "M77.1";
      U(    ;
      L     "R-W Asse Y Foratrice".QAttualeAsseY;
      L     "Scambio dati OP".QuotaBaseAsseY;
      <=D   ;
      )     ;
      =     "M75.4";
NETWORK
TITLE =Asse X in Movimento verso il Settimo Posizionamento

      U     "M60.1";
      U     "M75.4";
      U(    ;
      ON    "R-W Asse X Foratrice".IMEF;
      O(    ;
      L     "R-W Asse X Foratrice".QAttualeAsseX;
      L     "Scambio dati OP".Q7AsseXForatrice;
      ==D   ;
      )     ;
      )     ;
      UN    "M75.6";
      UN    "M77.1";
      =     "M75.5";
NETWORK
TITLE =Asse X Settimo Posizionamento Raggiunto

      U     "M60.1";
      U     "M75.5";
      U     "R-W Asse X Foratrice".RLPDR;
      U(    ;
      L     "R-W Asse X Foratrice".QAttualeAsseX;
      L     "Scambio dati OP".Q7AsseXForatrice;
      ==D   ;
      )     ;
      S     "M75.6";
      U     "M77.1";
      R     "M75.6";
      NOP   0;
NETWORK
TITLE =Com Aut Start Settimo Posizionamento Asse Z

      U     "M30.0";
      U     "M60.1";
      U     "M61.1";
      U     "EV104";
      U     "M12.7";
      U     "M75.1";
      UN    "M76.1";
      UN    "M77.1";
      U(    ;
      L     "R-W Asse Y Foratrice".QAttualeAsseY;
      L     "Scambio dati OP".QuotaBaseAsseY;
      <=D   ;
      )     ;
      =     "M75.7";
NETWORK
TITLE =Asse Z in Movimento verso il Settimo Posizionamento

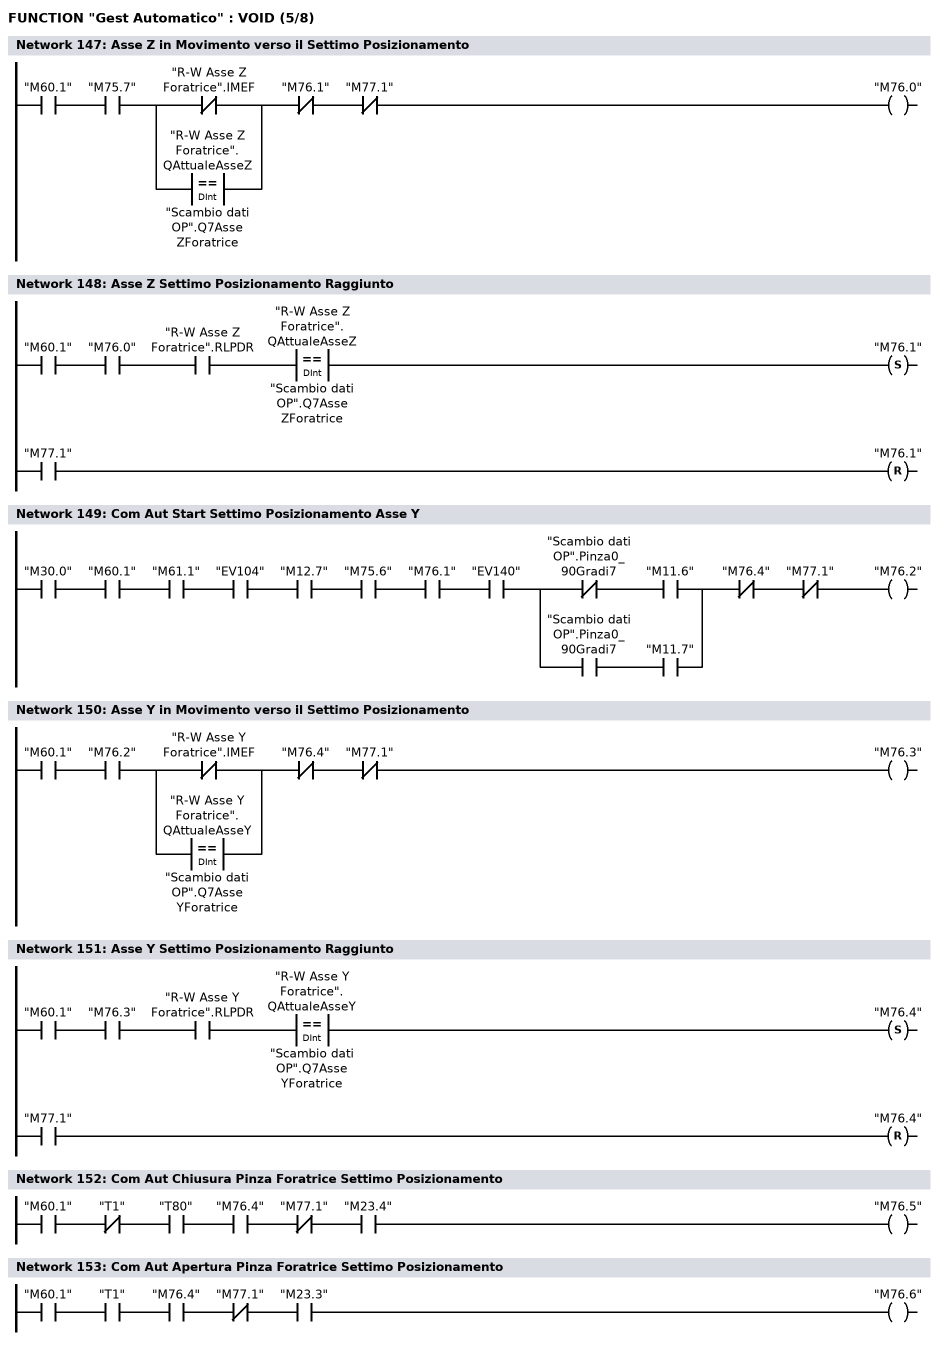
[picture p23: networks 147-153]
      U     "M60.1";
      U     "M75.7";
      U(    ;
      ON    "R-W Asse Z Foratrice".IMEF;
      O(    ;
      L     "R-W Asse Z Foratrice".QAttualeAsseZ;
      L     "Scambio dati OP".Q7AsseZForatrice;
      ==D   ;
      )     ;
      )     ;
      UN    "M76.1";
      UN    "M77.1";
      =     "M76.0";
NETWORK
TITLE =Asse Z Settimo Posizionamento Raggiunto

      U     "M60.1";
      U     "M76.0";
      U     "R-W Asse Z Foratrice".RLPDR;
      U(    ;
      L     "R-W Asse Z Foratrice".QAttualeAsseZ;
      L     "Scambio dati OP".Q7AsseZForatrice;
      ==D   ;
      )     ;
      S     "M76.1";
      U     "M77.1";
      R     "M76.1";
      NOP   0;
NETWORK
TITLE =Com Aut Start Settimo Posizionamento Asse Y

      U     "M30.0";
      U     "M60.1";
      U     "M61.1";
      U     "EV104";
      U     "M12.7";
      U     "M75.6";
      U     "M76.1";
      U     "EV140";
      U(    ;
      UN    "Scambio dati OP".Pinza0_90Gradi7;
      U     "M11.6";
      O     ;
      U     "Scambio dati OP".Pinza0_90Gradi7;
      U     "M11.7";
      )     ;
      UN    "M76.4";
      UN    "M77.1";
      =     "M76.2";
NETWORK
TITLE =Asse Y in Movimento verso il Settimo Posizionamento

      U     "M60.1";
      U     "M76.2";
      U(    ;
      ON    "R-W Asse Y Foratrice".IMEF;
      O(    ;
      L     "R-W Asse Y Foratrice".QAttualeAsseY;
      L     "Scambio dati OP".Q7AsseYForatrice;
      ==D   ;
      )     ;
      )     ;
      UN    "M76.4";
      UN    "M77.1";
      =     "M76.3";
NETWORK
TITLE =Asse Y Settimo Posizionamento Raggiunto

      U     "M60.1";
      U     "M76.3";
      U     "R-W Asse Y Foratrice".RLPDR;
      U(    ;
      L     "R-W Asse Y Foratrice".QAttualeAsseY;
      L     "Scambio dati OP".Q7AsseYForatrice;
      ==D   ;
      )     ;
      S     "M76.4";
      U     "M77.1";
      R     "M76.4";
      NOP   0;
NETWORK
TITLE =Com Aut Chiusura Pinza Foratrice Settimo Posizionamento

      U     "M60.1";
      UN    "T1";
      U     "T80";
      U     "M76.4";
      UN    "M77.1";
      U     "M23.4";
      =     "M76.5";
NETWORK
TITLE =Com Aut Apertura Pinza Foratrice Settimo Posizionamento

      U     "M60.1";
      U     "T1";
      U     "M76.4";
      UN    "M77.1";
      U     "M23.3";
      =     "M76.6";
NETWORK
TITLE =Com Aut Start Posizionamento Base Asse Y dopo Settima Foratura

      U     "M60.1";
      U     "M76.6";
      U     "T2";
      U     "EV140";
      UN    "M77.1";
      =     "M76.7";
      =     "M56.7";
NETWORK
TITLE =Asse Y in Movimento verso Posizione Base dopo Settima Foratura

      U     "M60.1";
      U     "M76.7";
      U(    ;
      ON    "R-W Asse Y Foratrice".IMEF;
      O(    ;
      L     "R-W Asse Y Foratrice".QAttualeAsseY;
      L     "Scambio dati OP".QuotaBaseAsseY;
      ==D   ;
      )     ;
      )     ;
      UN    "M77.1";
      =     "M77.0";
NETWORK
TITLE =Asse Y Posizione Base dopo Settima Foratura Raggiunta

      U     "M60.1";
      U     "M77.0";
      U     "R-W Asse Y Foratrice".RLPDR;
      U(    ;
      L     "R-W Asse Y Foratrice".QAttualeAsseY;
      L     "Scambio dati OP".QuotaBaseAsseY;
      ==D   ;
      )     ;
      S     "M77.1";
      U     "M60.1";
      UN    "M61.1";
      R     "M77.1";
      NOP   0;
NETWORK
TITLE =Tempo Aut Chiusura Pinza Foratura

      U(    ;
      U     "M60.1";
      U     "EV141";
      O     "T1";
      )     ;
      U(    ;
      U     "M64.4";
      UN    "M65.1";
      O     ;
      U     "M66.4";
      UN    "M67.1";
      O     ;
      U     "M68.4";
      UN    "M69.1";
      O     ;
      U     "M70.4";
      UN    "M71.1";
      O     ;
      U     "M72.4";
      UN    "M73.1";
      O     ;
      U     "M74.4";
      UN    "M75.1";
      O     ;
      U     "M76.4";
      UN    "M77.1";
      )     ;
      L     "Scambio dati OP".TempChiPinzaFor;
      SE    "T1";
      NOP   0;
      NOP   0;
      NOP   0;
      NOP   0;
NETWORK
TITLE =Tempo Aut Apertura Pinza Foratura

      U(    ;
      U     "M60.1";
      U     "T1";
      U     "EV140";
      O     "T2";
      )     ;
      U(    ;
      U     "M64.4";
      UN    "M65.1";
      O     ;
      U     "M66.4";
      UN    "M67.1";
      O     ;
      U     "M68.4";
      UN    "M69.1";
      O     ;
      U     "M70.4";
      UN    "M71.1";
      O     ;
      U     "M72.4";
      UN    "M73.1";
      O     ;
      U     "M74.4";
      UN    "M75.1";
      O     ;
      U     "M76.4";
      UN    "M77.1";
      )     ;
      L     "Scambio dati OP".TempApePinzaFor;
      SE    "T2";
      NOP   0;
      NOP   0;
      NOP   0;
      NOP   0;
NETWORK
TITLE =Tempo di Ritardo Chiusura Pinza in Tutti i Posizionamenti

      U     "M60.1";
      U(    ;
      U     "M64.4";
      UN    "M65.1";
      O     ;
      U     "M66.4";
      UN    "M67.1";
      O     ;
      U     "M68.4";
      UN    "M69.1";
      O     ;
      U     "M70.4";
      UN    "M71.1";
      O     ;
      U     "M72.4";
      UN    "M73.1";
      O     ;
      U     "M74.4";
      UN    "M75.1";
      O     ;
      U     "M76.4";
      UN    "M77.1";
      O     ;
      U     M     78.4;
      UN    M     79.1;
      )     ;
      L     S5T#1S;
      SE    "T80";
      NOP   0;
      NOP   0;
      NOP   0;
      NOP   0;
NETWORK
TITLE =Fine Ciclo Foratrice

      U     "M65.1";
      U(    ;
      U     "M67.1";
      U(    ;
      U     "M69.1";
      U     "M71.1";
      U     "M73.1";
      U(    ;
      U     "M75.1";
      U     "M77.1";
      O     "M30.1";
      )     ;
      O     "M30.2";
      )     ;
      O     "M30.3";
      )     ;
      S     "M77.2";
      U     "M60.1";
      UN    "M61.1";
      R     "M77.2";
      NOP   0;
NETWORK
TITLE =Com Aut Indietro Bloccaggio Zona Foratrice

      U     "M60.1";
      U(    ;
      O     "M77.2";
      ON    "M61.1";
      )     ;
      U     "M23.0";
      U(    ;
      L     "R-W Asse Y Foratrice".QAttualeAsseY;
      L     "Scambio dati OP".QuotaBaseAsseY;
      <=D   ;
      )     ;
      =     "M77.3";
NETWORK
TITLE =Com Aut Indietro Fermo Zona Foratrice

      U     "M60.1";
      U     "M77.2";
      UN    "M61.2";
      U     "M13.3";
      U     "M13.4";
      U     "M13.7";
      U     "M22.6";
      U(    ;
      L     "R-W Asse Y Foratrice".QAttualeAsseY;
      L     "Scambio dati OP".QuotaBaseAsseY;
      <=D   ;
      )     ;
      =     "M77.4";
NETWORK
TITLE =Com Aut Avanti Fermo Zona Ribaltatore

      U     "M60.1";
      UN    "M61.2";
      U     "M13.3";
      U     "M13.4";
      U     "M13.7";
      U     "M24.3";
      =     "M80.0";
NETWORK
TITLE =Com Aut Rotazione Ribaltatore al Prelievo per Prelevare

      U     "M60.1";
      U     "M61.2";
      UN    "M80.5";
      UN    "M81.2";
      U     "M23.5";
      =     "M80.1";
NETWORK
TITLE =Com Aut Indietro Fermo Zona Ribaltatore

      U     "M60.1";
      U     "M61.2";
      U     "EV106";
      UN    "M80.5";
      UN    "M81.2";
      U     "M24.4";
      =     "M81.4";
NETWORK
TITLE =Com Aut Chiusura Pinza Ribaltatore

      U     "M60.1";
      U     "M61.2";
      U     "EV115";
      UN    "M80.5";
      UN    "M81.2";
      U     "M23.7";
      =     "M80.2";
NETWORK
TITLE =Com Aut Salita Ribaltatore

      U     "M60.1";
      U     "EV110";
      U     "M13.5";
      UN    "M80.5";
      UN    "M81.2";
      U     "M24.1";
      =     "M80.3";
NETWORK
TITLE =Com Aut Rotazione Ribaltatore allo Scarico

      U     "M60.1";
      U     "EV112";
      UN    "M80.5";
      UN    "M81.2";
      U     "M23.6";
      =     "M80.4";
NETWORK
TITLE =Scarico Avvenuto

      U(    ;
      U     "M60.1";
      U     "EV107";
      U     "EV110";
      U     "M13.3";
      UN    "M81.2";
      L     "Scambio dati OP".TempRibalVasc;
      SE    "T36";
      NOP   0;
      NOP   0;
      NOP   0;
      U     "T36";
      )     ;
      S     "M80.5";
      U     "M81.2";
      R     "M80.5";
      NOP   0;
NETWORK
TITLE =Com Aut Rotazione Ribaltatore al Prelievo per Depositare

      U     "M60.1";
      U     "M80.5";
      U     "EV107";
      UN    "M81.2";
      U     "M23.5";
      =     "M80.6";
NETWORK
TITLE =Com Aut Discesa Ribaltatore

      U     "M60.1";
      U     "M80.5";
      U     "EV106";
      UN    "M81.2";
      U     "M24.2";
      =     "M80.7";
NETWORK
TITLE =Com Aut Apertura Pinze Ribaltatore

      U     "M60.1";
      U     "M80.5";
      U     "EV113";
      U     "M13.7";
      UN    "M81.2";
      U     "M24.0";
      =     "M81.0";
NETWORK
TITLE =Com Aut Avanti Fermo Zona Ribaltatore

      U     "M60.1";
      U     "M80.5";
      U     "EV111";
      U     "M13.4";
      UN    "M81.2";
      U     "M24.3";
      =     "M81.5";
NETWORK
TITLE =Com Aut Rotazione Ribaltatore allo Scarico

      U     "M60.1";
      U     "M80.5";
      U     "EV111";
      U     "EV114";
      U     "M13.1";
      UN    "M81.2";
      U     "M23.6";
      =     "M81.1";
NETWORK
TITLE =Fine Ciclo Ribaltatore

      U     "M60.1";
      U     "M80.5";
      U     "M13.3";
      U     "M13.4";
      U     "M13.7";
      S     "M81.2";
      UN    "M61.2";
      U     "EV114";
      U     "M13.3";
      U     "M13.4";
      U     "M13.7";
      R     "M81.2";
      NOP   0;
NETWORK
TITLE =Com Aut Indietro Fermo Zona Ribaltatore

      U     "M60.1";
      U     "M61.2";
      U     "M81.2";
      UN    "M85.5";
      U     "M24.4";
      =     "M81.3";
NETWORK
TITLE ======== Ciclo Automatico Zona Tampografia 1 =======



NETWORK
TITLE =Troppo Pieno Nastro Tampografie

      U(    ;
      UN    "SL290";
      U     "SL290B";
      U     "FT155";
      L     S5T#1S;
      SE    T     49;
      NOP   0;
      NOP   0;
      NOP   0;
      U     T     49;
      )     ;
      L     S5T#0MS;
      SA    T     50;
      NOP   0;
      NOP   0;
      NOP   0;
      U     T     50;
      =     "M85.5";
NETWORK
TITLE =Presenza Pezzo in Entrata Zona Tampografia 1

      O(    ;
      U(    ;
      U     "SL313";
      UN    "SL290";
      U     "SL290B";
      U     "FT182";
      L     S5T#1S500MS;
      SE    T     37;
      NOP   0;
      NOP   0;
      NOP   0;
      U     T     37;
      )     ;
      L     S5T#2S;
      SA    T     38;
      NOP   0;
      NOP   0;
      NOP   0;
      U     T     38;
      )     ;
      O(    ;
      U(    ;
      UN    "SL313";
      UN    "SL290";
      U     "SL290B";
      U     "FT182";
      L     S5T#1S500MS;
      SE    T     76;
      NOP   0;
      NOP   0;
      NOP   0;
      U     T     76;
      )     ;
      L     S5T#10S;
      SA    T     75;
      NOP   0;
      NOP   0;
      NOP   0;
      U     T     75;
      )     ;
      =     "M83.0";
NETWORK
TITLE =Presenza Pezzo Zona Tampografia 1

      U(    ;
      UN    "SL290";
      U     "SL290B";
      U     "FT190";
      L     S5T#1S500MS;
      SE    T     39;
      NOP   0;
      NOP   0;
      NOP   0;
      U     T     39;
      )     ;
      L     S5T#2S;
      SA    T     40;
      NOP   0;
      NOP   0;
      NOP   0;
      U     T     40;
      =     "M83.1";
NETWORK
TITLE =Presenza Pezzo Zona di Spostamento da N.Orizzontale a Verticale

      U(    ;
      UN    "SL290";
      U     "SL290B";
      U     "FT185";
      L     S5T#1S500MS;
      SE    T     41;
      NOP   0;
      NOP   0;
      NOP   0;
      U     T     41;
      )     ;
      L     S5T#0MS;
      SA    T     42;
      NOP   0;
      NOP   0;
      NOP   0;
      U     T     42;
      =     "M83.2";
NETWORK
TITLE =Com Aut Avanti Cadenziatore in Entrata Zona Tampografia 1

      U     "M60.1";
      UN    "M83.0";
      U     "M24.7";
      =     "M83.3";
NETWORK
TITLE =Com Aut Indietro Cadenziatore in Entrata Zona Tampografia 1

      U     "M60.1";
      U     "M83.0";
      U(    ;
      U     "SL313";
      UN    "M83.1";
      U     "EV162";
      UN    "M84.3";
      O     ;
      UN    "SL313";
      UN    "M83.2";
      )     ;
      U     "M15.3";
      U     "M25.0";
      =     "M83.4";
NETWORK
TITLE =Com Aut Avanti Fermo Zona Tampografia 1

      U     "M60.1";
      UN    "M83.1";
      U     "M14.6";
      U     "M15.3";
      UN    "M85.6";
      U     "M25.1";
      =     "M83.5";
NETWORK
TITLE =Com Aut Avanti Corsa Avvicinamento Zona Tampografia 1

      U     "M60.1";
      U     "M83.1";
      U     "EV162";
      UN    "M84.3";
      UN    "M85.6";
      U     "M25.5";
      =     "M83.6";
NETWORK
TITLE =Com Aut Chiusura Pinza Zona Tampografia 1

      U     "M60.1";
      U     "EV166";
      UN    "M84.3";
      UN    "M85.6";
      U     "M25.4";
      =     "M83.7";
NETWORK
TITLE =Com Aut Indietro Fermo Zona Tampografia 1

      U     "M60.1";
      U     "EV165";
      UN    "M84.3";
      UN    "M85.6";
      U     "M25.2";
      =     "M85.3";
NETWORK
TITLE =Com Aut Avanti Corsa Lavoro Zona Tampografia 1

      U     "M60.1";
      U     "EV165";
      UN    "M84.3";
      UN    "M85.6";
      U     "M25.7";
      =     "M84.0";
NETWORK
TITLE =Com Aut Start Tampografia 1

      U     "M60.1";
      U     "EV170";
      U     "M15.4";
      U     "INT214";
      UN    "M84.2";
      UN    "M84.3";
      S     "M84.1";
      U(    ;
      O     "M84.2";
      O     "M84.3";
      O     "M85.6";
      )     ;
      R     "M84.1";
      NOP   0;
NETWORK
TITLE =Tampografia 1 in Esecuzione

      U     "M60.1";
      U     "M84.1";
      UN    "M84.3";
      UN    "INT214";
      S     "M84.2";
      U(    ;
      O     "M84.3";
      O     "M85.6";
      )     ;
      R     "M84.2";
      NOP   0;
NETWORK
TITLE =Tampografata Zona Tampografia 1 Terminata

      U     "M60.1";
      U     "M84.2";
      U     "INT214";
      S     "M84.3";
      U(    ;
      UN    "M83.1";
      U     "M14.6";
      U     "M15.1";
      U     "M15.3";
      UN    "M15.4";
      UN    "M15.5";
      O     "M85.6";
      )     ;
      R     "M84.3";
      NOP   0;
NETWORK
TITLE =Com Aut Indietro Corsa Lavoro Zona Tampografia 1

      U     "M60.1";
      U     "M84.3";
      UN    "M85.6";
      U     "M26.0";
      =     "M84.4";
NETWORK
TITLE =Com Aut Avanti Fermo Zona Tampografia 1

      U     "M60.1";
      U     "M84.3";
      U     "EV171";
      U     "M15.2";
      UN    "M85.6";
      U     "M15.5";
      =     "M85.4";
NETWORK
TITLE =Com Aut Apertura Pinza Zona Tampografia 1

      U     "M60.1";
      U     "M84.3";
      U     "EV171";
      UN    "M83.2";
      UN    "M85.6";
      U     "M25.3";
      =     "M84.5";
NETWORK
TITLE =Com Aut Indietro Corsa Avvicinamento Zona Tampografia 1

      U     "M60.1";
      U     "M84.3";
      U     "EV164";
      UN    "M85.6";
      U     "M25.6";
      =     "M84.6";
NETWORK
TITLE =Fine Ciclo Tampografia 1

      U(    ;
      U     "M60.1";
      U     "M84.3";
      U     "EV167";
      U     "M14.6";
      U     "M15.3";
      O     ;
      UN    "SL290";
      U     "SL290B";
      UN    "SL313";
      U     "M14.6";
      U     "M15.3";
      )     ;
      S     "M85.6";
      U     "SL313";
      UN    "M83.1";
      R     "M85.6";
      NOP   0;
NETWORK
TITLE =Com Aut Indietro Fermo Zona Tampografia 1

      U     "M60.1";
      U     "M85.6";
      U     "M83.1";
      UN    "M83.2";
      U     "M25.2";
      =     "M84.7";
NETWORK
TITLE =Com Aut Avanti Braccio Spostam da N.Orizzontale a N.Verticale

      U     "M60.1";
      U     "M83.2";
      UN    "M87.0";
      U     "EV234";
      U     "M26.1";
      =     "M85.0";
NETWORK
TITLE =Com Aut Indietro Braccio Spostam da N.Orizzontale a N.Verticale

      U     "M60.1";
      U     "M26.2";
      =     "M85.1";
NETWORK
TITLE ======== Ciclo Automatico Zona Tampografia 2 =======



NETWORK
TITLE =Presenza Pezzo Zona Tampografia 2

      U(    ;
      UN    "SL290";
      U     "SL290B";
      U     "FT250";
      L     S5T#1S500MS;
      SE    T     43;
      NOP   0;
      NOP   0;
      NOP   0;
      U     T     43;
      )     ;
      L     S5T#2S;
      SA    T     44;
      NOP   0;
      NOP   0;
      NOP   0;
      U     T     44;
      =     "M87.0";
NETWORK
TITLE =Com Aut Start Nastro Verticale

      U     "M60.1";
      U     "M22.2";
      =     "M87.1";
NETWORK
TITLE =Com Aut Discesa Fermo Zona Tampografia 2

      U     "M60.1";
      UN    "M87.0";
      U(    ;
      ON    "M89.4";
      ON    "SL314";
      )     ;
      U     "M27.1";
      =     "M88.0";
NETWORK
TITLE =Com Aut Avanti Corsa di Avvicinamento Tampografia 2

      U     "M60.1";
      U     "M87.0";
      UN    "M88.7";
      UN    "M89.4";
      U     "M27.3";
      =     "M88.1";
NETWORK
TITLE =Com Aut Avanti Corsa di Lavoro Tampografia 2

      U     "M60.1";
      U     "M87.0";
      UN    "M88.7";
      UN    "M89.4";
      U     "M27.5";
      =     "M88.2";
NETWORK
TITLE =Com Aut Chiusura Pinza Tampografia 2

      U     "M60.1";
      U     "M87.0";
      U     "EV236";
      U     "EV262";
      UN    "M88.7";
      UN    "M89.4";
      U     "M27.0";
      =     "M88.3";
NETWORK
TITLE =Com Aut Discesa Fermo Antiribaltamento Monoblocco Tampografia 2

      U     "M60.1";
      U     "M87.0";
      U     "EV236";
      U     "EV262";
      UN    "M88.7";
      UN    "M89.4";
      U     "M26.6";
      =     "M88.4";
NETWORK
TITLE =Com Aut Start Tampografia 2

      U     "M60.1";
      U     "INT267";
      U     "M87.0";
      U     "M15.7";
      U     "M16.2";
      U     "M16.4";
      U     "M16.6";
      S     "M88.5";
      U(    ;
      O     "M88.6";
      O     "M88.7";
      O     "M89.4";
      )     ;
      R     "M88.5";
      NOP   0;
NETWORK
TITLE =Tamopografia 2 in Esecuzione

      U     "M60.1";
      U     "M88.5";
      UN    "INT267";
      S     "M88.6";
      U(    ;
      O     "M88.7";
      O     "M89.4";
      )     ;
      R     "M88.6";
      NOP   0;
NETWORK
TITLE =Tampografia 2 Eseguita

      U     "M60.1";
      U     "M88.6";
      U     "INT267";
      S     "M88.7";
      U     "M89.4";
      R     "M88.7";
      NOP   0;
NETWORK
TITLE =Com Aut Salita Fermo Antiribaltamento Monoblocco Tampografia 2

      U     "M60.1";
      U(    ;
      O     "M88.7";
      ON    "M87.0";
      )     ;
      UN    "M89.4";
      U     "M26.5";
      =     "M89.0";
NETWORK
TITLE =Com Aut Indietro Corsa di Lavoro Tampografia 2

      U     "M60.1";
      U(    ;
      O     "M88.7";
      ON    "M87.0";
      )     ;
      U     "EV230";
      UN    "M89.4";
      U     "M27.6";
      =     "M89.1";
NETWORK
TITLE =Com Aut Apertura Pinza Tampografia 2

      U     "M60.1";
      U(    ;
      O     "M88.7";
      ON    "M87.0";
      )     ;
      U     "EV263";
      UN    "M89.4";
      U     "M26.7";
      =     "M89.2";
NETWORK
TITLE =Com Aut Indietro Corsa di Avvicinamento Tampografia 2

      U     "M60.1";
      U(    ;
      O     "M88.7";
      ON    "M87.0";
      )     ;
      U     "EV232";
      UN    "M89.4";
      U     "M27.4";
      =     "M89.3";
NETWORK
TITLE =Fine Ciclo Tampografia 2

      U(    ;
      U     "M60.1";
      U     "M88.7";
      U     "M15.6";
      U     "M16.3";
      U     "M16.5";
      U     "EV263";
      O     ;
      UN    "SL290";
      U     "SL290B";
      UN    "SL314";
      U     "M15.6";
      U     "M16.3";
      U     "M16.5";
      U     "EV263";
      )     ;
      S     "M89.4";
      U     "SL314";
      UN    "M87.0";
      R     "M89.4";
      NOP   0;
NETWORK
TITLE =Com Aut Salita Fermo Zona Tampografia 2

      U     "M60.1";
      U     "M89.4";
      U     "M87.0";
      U     "M27.2";
      U(    ;
      U     "Gest Rete Supervisore Q3".EscBoxingDX;
      UN    "M91.0";
      U     "EV227";
      U     "M17.1";
      O     ;
      U     "Gest Rete Supervisore Q3".EscBoxingSX;
      UN    "M91.1";
      U     "EV221";
      U     "M17.0";
      U     "M17.3";
      )     ;
      UN    "M89.6";
      UN    "M89.7";
      =     "M89.5";
NETWORK
TITLE =Memoria Sgancio Monoblocco da Tampografia 2 per Boxing DX

      U     "M89.5";
      U     "Gest Rete Supervisore Q3".EscBoxingDX;
      UN    "M91.0";
      U     "EV227";
      U     "M17.1";
      S     "M89.6";
      U     "M91.0";
      R     "M89.6";
      NOP   0;
NETWORK
TITLE =Memoria Sgancio Monoblocco da Tampografia 2 per Boxing SX

      U     "M89.5";
      U     "Gest Rete Supervisore Q3".EscBoxingSX;
      UN    "M91.1";
      U     "EV221";
      U     "M17.0";
      U     "M17.3";
      S     "M89.7";
      U     "M91.1";
      R     "M89.7";
      NOP   0;
NETWORK
TITLE ======== Ciclo Automatico Bracci di Spost =======



NETWORK
TITLE =Presenza Pezzo Braccio Spost da N.Verticale a N.1

      U(    ;
      UN    "SL290";
      U     "SL290B";
      U     "FT242";
      L     S5T#500MS;
      SE    T     45;
      NOP   0;
      NOP   0;
      NOP   0;
      U     T     45;
      )     ;
      L     S5T#0MS;
      SA    T     46;
      NOP   0;
      NOP   0;
      NOP   0;
      U     T     46;
      =     "M91.0";
NETWORK
TITLE =Presenza Pezzo Braccio Spost da N.Verticale a N.3

      U(    ;
      UN    "SL290";
      U     "SL290B";
      U     "FT247";
      L     S5T#500MS;
      SE    T     47;
      NOP   0;
      NOP   0;
      NOP   0;
      U     T     47;
      )     ;
      L     S5T#0MS;
      SA    T     48;
      NOP   0;
      NOP   0;
      NOP   0;
      U     T     48;
      =     "M91.1";
NETWORK
TITLE =Com Aut Avanti Braccio di Spostam da N.Verticale a N.1

      U     "M60.1";
      UN    "M89.6";
      U(    ;
      U     "Gest Rete Supervisore Q3".EscBoxingDX;
      U(    ;
      U     "M91.0";
      UN    "Gest Rete Supervisore Q3".PPCBDX;
      O     ;
      UN    "M91.0";
      U     "Gest Rete Supervisore Q3".PPCBDX;
      UN    "Gest Rete Supervisore Q3".PPCBSX;
      )     ;
      ON    "Gest Rete Supervisore Q3".EscBoxingDX;
      )     ;
      U     "M28.1";
      L     S5T#1S;
      SE    T      4;
      NOP   0;
      NOP   0;
      NOP   0;
      U     T      4;
      =     "M91.2";
NETWORK
TITLE =Com Aut Avanti Braccio di Spostam da N.Verticale a N.3

      U     "M60.1";
      U     "Gest Rete Supervisore Q3".EscBoxingSX;
      U     "M91.1";
      UN    "Gest Rete Supervisore Q3".PPCBSX;
      U     "M27.7";
      L     S5T#1S;
      SE    T      5;
      NOP   0;
      NOP   0;
      NOP   0;
      U     T      5;
      =     "M91.3";
NETWORK
TITLE =Com Aut Indietro Braccio di Spostam da N.Verticale a N.1

      U     "M60.1";
      U     "Gest Rete Supervisore Q3".EscBoxingDX;
      UN    "M89.7";
      UN    "M91.0";
      U(    ;
      U(    ;
      O     "M91.0";
      O     "Gest Rete Supervisore Q3".PPCBSX;
      )     ;
      UN    "Gest Rete Supervisore Q3".PPCBDX;
      ON    "Gest Rete Supervisore Q3".EscBoxingSX;
      )     ;
      U     "M28.2";
      =     "M91.4";
NETWORK
TITLE =Com Aut Indietro Braccio di Spostam da N.Verticale a N.3

      U     "M60.1";
      U     "Gest Rete Supervisore Q3".EscBoxingSX;
      UN    "M91.1";
      U     "M17.2";
      U     "M28.0";
      =     "M91.5";
NETWORK
TITLE =

      UN    "M60.1";
      FP    M     59.0;
      R     "M56.1";
      R     "M56.2";
      R     "M56.3";
      R     "M56.4";
      R     "M56.5";
END_FUNCTION

